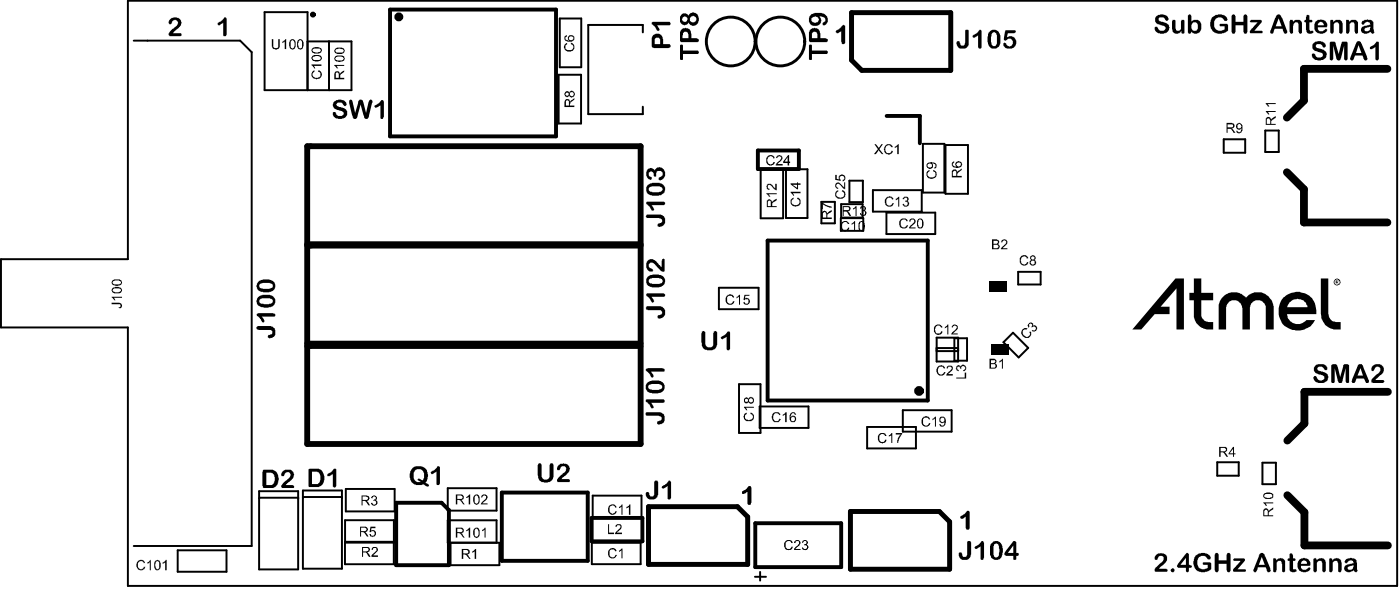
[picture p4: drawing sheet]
<svg xmlns="http://www.w3.org/2000/svg" width="119mm" height="50mm" viewBox="0 0 119 50" stroke-linecap="round" stroke-linejoin="round" font-family="sans-serif">
<g fill="none" stroke="#000" stroke-width=".17">
<path d="M10.9 .1h108.1v49.7h-108.1v-21.9h-10.8v-5.9h10.8zM11.4 3.5h9.1l.9 .9v42h-10M12.6 3.5h.1M26.2 3.5h3.7v4.2h-7.4v-6.7h3.7v6.7M28 3.5v4.2M47.6 6.4h1.9v4.1h-1.9zM47.7 1.6h1.8v4.1h-1.8zM54.7 2.8v-.7h-4.6v7.6h4.6v-.6M64.8 14.4h1.9v4.2h-1.9zM66.9 14.4h1.9v4.1h-1.9zM70 17.2h1.1v1.8h-1.1zM71.6 18.6h1.9v1h-1.9z"/>
<path d="M71.6 17.4h1.9v1.1h-1.9zM72.3 15.4h1.2v1.8h-1.2zM74.3 16.2h4.2v1.8h-4.2zM75.5 18.1h4.2v1.8h-4.2zM78.6 12.2h1.8v4.2h-1.8zM80.5 12.3h1.9v4.2h-1.9zM104.2 11.8h1.9v1.2h-1.9zM107.8 11.1h1.1v1.8h-1.1zM61.2 24.5h3.4v1.8h-3.4zM62.9 32.7h1.9v4.1h-1.9zM64.7 34.6h4.2v1.8h-4.2zM73.9 36.3h4.1v1.8h-4.1z"/>
<path d="M76.9 34.9h4.2v1.8h-4.2zM79.8 29.6h1.8M79.8 28.7h1.8v2h-1.8zM79.8 29.9h1.8M81.3 28.8h1.1v1.9h-1.1zM85.5 29.1l.8-.8 1.3 1.3-.8 .8zM86.7 23.1h1.9v1.1h-1.9zM103.7 39.3h1.8v1.2h-1.8zM107.5 39.4h1.2v1.8h-1.2zM15.1 46.8h4.2v1.8h-4.2zM22.1 41.8h3.3v6.6h-3.3zM25.4 42.3l-3.3 .1"/>
<path d="M25.8 41.7h3.3v6.7h-3.3zM29.1 42.3h-3.3M29.5 41.6h4.1v1.9h-4.1zM33.5 46.1h-4.1v1.9h4.1v-3.8h-4.1v2h4.1M38.1 41.5h4.2v1.9h-4.2zM42.3 46.2v-1.9h-4.2v1.9h4.4v1.9h-4.1v-1.9M50.4 46.2h4.2v1.8h-4.2zM50.5 42.2h4.1v1.8h-4.1zM64.3 49.1h.9M64.7 48.6v.8"/>
</g>
<path d="M26.2 12.4h28.4v8.4h-28.4zM26.2 29.4h28.4v8.4h-28.4zM26.2 20.9h28.4v8.3h-28.4z" fill="none" stroke="#000" stroke-width=".5"/>
<g fill="none" stroke="#000" stroke-width=".42">
<path d="M72.5 1.1h8.5v4.9h-7.6l-.9-.9zM55.2 43.1h7.6l.9 .9v4h-8.5zM72.4 43.5h7.6l.9 .9v4h-8.5z"/>
<circle cx="34" cy="1.4" r=".17"/>
</g>
<path d="M109.6 14.6l1.5 1.5v2.8h7.1M118.2 5.9h-7.1v2.7l-1.5 1.4M118.2 33.3h-7.1v2.7l-1.5 1.5M109.6 42.1l1.5 1.5v2.8h7.1" fill="none" stroke="#000" stroke-width=".66"/>
<path d="M33.2 .8h14.2v10.8h-14.2zM64.5 12.8h3.5v1.6h-3.5zM75.5 9.9h2.8v2.3M65.4 20.5h13.6v13.6h-13.6zM33.7 42.8h3.9l.6 .6v4.7h-4.5zM42.7 41.9h7.4v5.8h-7.4zM50.4 44h4.3v2h-4.3zM64.3 44.5h7.3v3.7h-7.3z" fill="none" stroke="#000" stroke-width=".33"/>
<g fill="#000">
<path d="M84.2 23.9h1.5v.9h-1.5z" fill-rule="evenodd"/>
<path d="M84.4 29.3h1.5v.9h-1.5z" fill-rule="evenodd"/>
</g>
<g fill="#000">
<path d="M14.4 1.7l.1-.1a.53 .53 0 0 1 .8 0 .53 .53 0 0 1 0 .8l-.6 .4h.7l.1 .2-1 .1a.24 .24 0 0 1-.1-.3 .24 .24 0 0 1 .1-.2l.3-.2a.35 .35 0 0 0 .3-.3 .35 .35 0 0 0-.2-.4l-.2 .1a.18 .18 0 0 1-.2 .3 .17 .17 0 0 1-.1-.3zM18.5 1.9l.3-.1 .2-.2a.15 .15 0 0 1 .2-.1 .15 .15 0 0 1 .1 .1v1.3a.15 .15 0 0 1-.1 .2 .15 .15 0 0 1-.2-.2v-1l-.2 .2a.13 .13 0 0 1-.2 .1 .13 .13 0 0 1-.1-.2zM23.1 3.3h.2v.5a.22 .22 0 0 0 .2 .3 .22 .22 0 0 0 .2-.3v-.5h.1v.5a.34 .34 0 0 1-.3 .4 .34 .34 0 0 1-.4-.4zM24 3.5l.4-.2v.9h-.2v-.7l-.2 .2zM26.6 6.1l.1-.1 .1 .1a.28 .28 0 0 0-.1 .4 .28 .28 0 0 0 .3 .1 .28 .28 0 0 0 .3-.2 .28 .28 0 0 0-.2-.3v-.1a.39 .39 0 0 1 .3 .5 .39 .39 0 0 1-.6 .2 .37 .37 0 0 1-.2-.6zM26.5 5.5h.9v.1h-.7l.2 .2h-.2zM28.4 8.7a.65 .65 0 0 1 1.1 .2 .21 .21 0 0 1-.2 .1 .21 .21 0 0 1-.2-.2 .33 .33 0 0 0-.5 .1l.3 .2a.55 .55 0 0 1 .6 .7 .69 .69 0 0 1-1.2-.1 .16 .16 0 0 1 .2-.2 .16 .16 0 0 1 .1 .2 .35 .35 0 0 0 .4 .2 .35 .35 0 0 0 .3-.3l-.4-.2a.5 .5 0 0 1-.5-.7zM28.5 5.5h.8v.1h-.6l.1 .2h-.1zM29.7 8.6l.1-.1h.2l.2 1.1 .3-.8a.24 .24 0 0 1 .2-.3 .24 .24 0 0 1 .3 .3l.2 .8 .2-.9a.18 .18 0 0 1 .2-.2 .18 .18 0 0 1 .1 .3l-.3 1a.24 .24 0 0 1-.2 .3 .24 .24 0 0 1-.2-.3l-.3-.9-.2 .9a.24 .24 0 0 1-.3 .3 .24 .24 0 0 1-.2-.3zM31.9 9l.5-.4a.15 .15 0 0 1 .2-.1 .15 .15 0 0 1 .1 .2v1.2a.14 .14 0 0 1-.2 .2 .13 .13 0 0 1-.1-.2v-.9l-.4 .2-.1-.1zM48.1 3.8l.1-.1 .1 .1a.28 .28 0 0 0-.1 .3 .28 .28 0 0 0 .4 .2 .25 .25 0 0 0 .2-.3 .25 .25 0 0 0-.2-.2v-.2a.42 .42 0 0 1 .2 .7 .42 .42 0 0 1-.7-.2zM55 18.3l1.1-.1a.52 .52 0 0 1 .6 .6 .52 .52 0 0 1-.7 .5v-.2l.1-.1a.22 .22 0 0 0 .3-.1 .22 .22 0 0 0-.2-.3l-1.1-.1-.1-.1z"/>
<path d="M55 17.2h1.5a.15 .15 0 0 1 .1 .1 .15 .15 0 0 1-.1 .1h-1l.2 .4a.11 .11 0 0 1-.1 .1 .11 .11 0 0 1-.1-.1l-.5-.4zM55.1 14.4a.38 .38 0 0 1 .7 .1 .51 .51 0 0 1 .7-.1 .51 .51 0 0 1 .1 .7 .26 .26 0 0 1-.2 .2 .26 .26 0 0 1-.3-.1v-.1a.32 .32 0 0 0 .3-.5 .3 .3 0 0 0-.5 0 .3 .3 0 0 0 0 .4h-.1a.25 .25 0 0 1-.2-.3 .23 .23 0 0 0-.4 0 .23 .23 0 0 0 .3 .3 .16 .16 0 0 1-.1 .3 .15 .15 0 0 1-.2-.1 .67 .67 0 0 1-.1-.8zM55.5 1.9h1.5a.15 .15 0 0 1 .1 .1 .15 .15 0 0 1-.2 .2h-.9l.2 .3-.1 .2-.3-.5-.3-.1zM57.9 3.8h.3v.5h1.2a.15 .15 0 0 1 .1 .2 .15 .15 0 0 1-.2 .1h-1.1v.5h-.2zM65.3 15.7a.49 .49 0 0 1 .7 .3v-.4h.2v.6l-.3-.1a.37 .37 0 0 0-.5-.3 .17 .17 0 0 0 0 .2 .17 .17 0 0 0 .2 .1h-.1h-.2zM65.3 13.4a.37 .37 0 0 1 .4-.2 .37 .37 0 0 1 .3 .2l-.1 .1a.27 .27 0 0 0-.4-.2 .27 .27 0 0 0-.1 .4 .29 .29 0 0 0 .2 .3 .29 .29 0 0 0 .3-.2h.1a.39 .39 0 0 1-.5 .2 .39 .39 0 0 1-.2-.5zM65.3 16.4h.9v.1h-.7l.1 .2h-.1zM66.2 13.3a.28 .28 0 0 1 .4 0 .28 .28 0 0 1-.2 .4l-.2 .2h.5v.2h-.6l.1-.3a.44 .44 0 0 0 .3-.5h-.1l-.3 .1zM67.3 17l.2-.2 .1 .1a.28 .28 0 0 0-.1 .4 .28 .28 0 0 0 .3 .1 .28 .28 0 0 0 .3-.2 .28 .28 0 0 0-.2-.3v-.1a.39 .39 0 0 1 .3 .5 .39 .39 0 0 1-.6 .2 .46 .46 0 0 1-.3-.5zM67.3 16.3h.9v.1h-.7l.1 .2h-.1zM68.9 3.8h.3v.5h1.1a.15 .15 0 0 1 .2 .2 .15 .15 0 0 1-.2 .1h-1.1v.5h-.3zM70 17.2l.5 .3 .3 .1v.1l-.3-.1-.4-.2v.4h-.1z"/>
<path d="M71.2 16.3l.1-.1 .1 .1a.27 .27 0 0 0-.2 .3 .27 .27 0 0 0 .4 .2 .28 .28 0 0 0 .3-.2 .28 .28 0 0 0-.2-.3v-.1a.39 .39 0 0 1 .3 .5 .39 .39 0 0 1-.6 .2 .42 .42 0 0 1-.2-.6zM71.2 15.6a.37 .37 0 0 1 .5 .2l.2 .1v-.4h.1v.6l-.3-.2a.27 .27 0 0 0-.2-.2 .27 .27 0 0 0-.3 .1l.2 .3a.28 .28 0 0 1-.3-.2 .28 .28 0 0 1 .1-.3zM71.1 14.9h.2v.3l.2 .1a.28 .28 0 0 1 .1-.4 .28 .28 0 0 1 .4 .2 .28 .28 0 0 1-.2 .3v-.1a.17 .17 0 0 0 .1-.2 .17 .17 0 0 0-.2-.1h-.2l.1 .4-.5-.1zM71.2 2.6l.3-.1 .3-.4 .2 .1v1.3a.18 .18 0 0 1-.2 .3 .18 .18 0 0 1-.2-.3v-.9l-.1 .1a.15 .15 0 0 1-.2 .1 .15 .15 0 0 1-.1-.2zM71.6 19a.38 .38 0 0 1 .4-.2 .38 .38 0 0 1 .3 .2h-.1a.3 .3 0 0 0-.4 0 .3 .3 0 0 0 0 .4 .25 .25 0 0 0 .2 .2 .25 .25 0 0 0 .2-.3l.1 .1a.4 .4 0 0 1-.5 .2 .4 .4 0 0 1-.2-.6zM72.5 19l.3-.2v.8h-.1v-.6l-.2 .1zM72.7 17.7l.3-.2v.9h-.1v-.7l-.2 .1zM73.3 17.6a.25 .25 0 0 1 .4 0 .25 .25 0 0 1 0 .3h-.1a.26 .26 0 0 1 0 .5 .26 .26 0 0 1-.3-.2v-.1a.16 .16 0 0 0 .2 .2 .16 .16 0 0 0 .2-.2 .16 .16 0 0 0-.2-.1v-.1a.14 .14 0 0 0 .2-.1 .14 .14 0 0 0-.2-.2 .14 .14 0 0 0-.1 .1h-.1zM74.5 12.3h.1l.3 .3 .2-.3h.1l-.3 .4 .3 .4h-.1l-.2-.3-.3 .3h-.2l.4-.4zM75.4 12.4a.38 .38 0 0 1 .3-.1 .38 .38 0 0 1 .3 .2h-.1a.29 .29 0 0 0-.4-.1 .29 .29 0 0 0-.1 .4 .28 .28 0 0 0 .3 .2 .28 .28 0 0 0 .3-.2 .14 .14 0 0 1 0 .2 .14 .14 0 0 1-.1 .1 .41 .41 0 0 1-.6-.1 .41 .41 0 0 1 .1-.6zM75.4 16.9a.33 .33 0 0 1 .4-.2 .33 .33 0 0 1 .3 .2l-.1 .1a.29 .29 0 0 0-.4-.2 .29 .29 0 0 0-.1 .4 .26 .26 0 0 0 .2 .3 .26 .26 0 0 0 .3-.2h.1a.4 .4 0 0 1-.5 .3 .4 .4 0 0 1-.2-.6zM76.2 12.5l.3-.2v.8h-.1v-.6l-.2 .1z"/>
<path d="M76.3 16.9l.3-.2v.9h-.1v-.7l-.2 .1zM76.6 18.8a.4 .4 0 0 1 .7 0h-.1a.29 .29 0 0 0-.4-.1 .29 .29 0 0 0-.1 .4 .26 .26 0 0 0 .3 .2 .26 .26 0 0 0 .2-.2l.1 .1a.42 .42 0 0 1-.5 .2 .42 .42 0 0 1-.2-.6zM76.9 16.9a.24 .24 0 0 1 .3-.2 .24 .24 0 0 1 .1 .4 .26 .26 0 0 1 0 .4 .26 .26 0 0 1-.4-.1l.1-.1a.18 .18 0 0 0 .2 .2 .18 .18 0 0 0 .1-.2 .18 .18 0 0 0-.2-.1v-.1a.14 .14 0 0 0 .2-.1 .14 .14 0 0 0-.1-.2 .14 .14 0 0 0-.2 .1h-.1zM77.5 18.7a.28 .28 0 0 1 .4 0 .28 .28 0 0 1-.1 .4l-.2 .2h.4v.1h-.6v-.1l.3-.2a.23 .23 0 0 0 .2-.2 .23 .23 0 0 0-.2-.2h-.1v.1h-.2zM79 14.6l.1-.1 .1 .1a.3 .3 0 0 0-.1 .4 .3 .3 0 0 0 .4 0 .25 .25 0 0 0 .2-.2 .25 .25 0 0 0-.2-.2v-.1l.2 .1a.38 .38 0 0 1 0 .4 .38 .38 0 0 1-.4 .2 .4 .4 0 0 1-.4-.2 .4 .4 0 0 1 .1-.4zM82.2 2.6h.3v.9a.53 .53 0 0 1-.5 .6 .53 .53 0 0 1-.6-.5 .18 .18 0 0 1 .3-.1 .18 .18 0 0 1 .1 .3l.1 .1a.24 .24 0 0 0 .3-.3zM82.8 3l.5-.2v-.2a.13 .13 0 0 1 .2-.1 .13 .13 0 0 1 .1 .2v1.3a.15 .15 0 0 1-.1 .1 .15 .15 0 0 1-.2-.1v-1l-.2 .2a.12 .12 0 0 1-.2 0 .12 .12 0 0 1-.1-.2zM85.6 2.6h.8a.13 .13 0 0 1 .1 .1 .13 .13 0 0 1-.2 .1h-.5v.4a.53 .53 0 0 1 .8 .4 .53 .53 0 0 1-.7 .5 .36 .36 0 0 1-.4-.4h.1a.39 .39 0 0 0 .5 .2 .32 .32 0 0 0 .1-.5 .32 .32 0 0 0-.4 0l-.1 .1a.14 .14 0 0 1-.2-.1 .14 .14 0 0 1 0-.2zM98.4 1.4a.62 .62 0 0 1 .7-.2 .62 .62 0 0 1 .4 .5 .23 .23 0 0 1-.4-.2 .25 .25 0 0 0-.3 0 .25 .25 0 0 0-.1 .3l.4 .1a.52 .52 0 0 1 .5 .6 .52 .52 0 0 1-.7 .4 .45 .45 0 0 1-.5-.6h.2a.36 .36 0 0 0 .3 .3 .36 .36 0 0 0 .4-.3l-.4-.2a.44 .44 0 0 1-.5-.2 .44 .44 0 0 1 0-.5zM99.9 1.7h.2v.7a.26 .26 0 0 0 .4 .2 .26 .26 0 0 0 .1-.4v-.3a.15 .15 0 0 1 .1-.2 .15 .15 0 0 1 .2 .2v.8a.14 .14 0 0 1-.2 .2 .14 .14 0 0 1-.1-.2 .42 .42 0 0 1-.5 .2 .42 .42 0 0 1-.3-.5zM103.2 1.5a.77 .77 0 0 1 1.4 .2l-.1 .1h-.2a.52 .52 0 0 0-.7-.2 .58 .58 0 0 0-.1 .8 .58 .58 0 0 0 .8 .1v-.3h-.3a.11 .11 0 0 1-.1 0 .11 .11 0 0 1 .1-.2h.5l.1 .1v.4a.86 .86 0 0 1-1.2 .2 .86 .86 0 0 1-.2-1.2zM104.9 1.3a.14 .14 0 0 1 .2-.1 .14 .14 0 0 1 .1 .2v.5h.7v-.6a.14 .14 0 0 1 .2-.1 .14 .14 0 0 1 .1 .2v1.3a.17 .17 0 0 1-.1 .2 .17 .17 0 0 1-.2-.2v-.5h-.7v.5a.17 .17 0 0 1-.1 .2 .17 .17 0 0 1-.2-.2z"/>
<path d="M106.5 1.8v-.1h1v.2l-.7 .7h.6a.11 .11 0 0 1 .2 .1 .11 .11 0 0 1-.2 .1h-.9a.11 .11 0 0 1-.1-.1 .11 .11 0 0 1 .1-.1l.6-.7h-.6zM107.8 9.4h.9v.1h-.7l.1 .2h-.1zM107.8 8.8h.9v.1h-.7l.1 .1-.1 .1zM109.9 1.7a.14 .14 0 0 1 .2 0 .14 .14 0 0 1 0 .2 .41 .41 0 0 1 .5-.2 .41 .41 0 0 1 .3 .5v.5a.15 .15 0 0 1-.2 .2 .15 .15 0 0 1-.1-.2v-.5a.24 .24 0 0 0-.2-.3 .24 .24 0 0 0-.3 .3v.5a.15 .15 0 0 1-.1 .2 .15 .15 0 0 1-.2-.2zM111.3 1.3h.1a.14 .14 0 0 1 .1 0 .14 .14 0 0 1 0 .2v.2h.2a.11 .11 0 0 1 .1 .1 .11 .11 0 0 1-.2 .1h-.1v.5a.19 .19 0 0 0 .1 .2 .19 .19 0 0 0 .2 0 .22 .22 0 0 1-.1 .3 .22 .22 0 0 1-.3-.1h-.1l-.1-.3v-.6l-.1-.1 .1-.1zM111.8 3.7h.1a.65 .65 0 0 1 1 .2l-.1 .1h-.1a.34 .34 0 0 0-.3-.2 .34 .34 0 0 0-.3 .1l.1 .2 .3 .1a.49 .49 0 0 1 .5 .5 .49 .49 0 0 1-.6 .4 .54 .54 0 0 1-.7-.5h.3a.34 .34 0 0 0 .3 .3 .34 .34 0 0 0 .4-.3l-.4-.2a.52 .52 0 0 1-.5-.6zM113.3 1.7a.14 .14 0 0 1 .2 0 .14 .14 0 0 1 .1 .2 .45 .45 0 0 1 .5-.2 .45 .45 0 0 1 .3 .5v.5l-.1 .2-.2-.1v-.6a.26 .26 0 0 0-.4-.3 .26 .26 0 0 0-.1 .4v.4l-.1 .2h-.1l-.1-.1zM113.3 3.6v-.1h.4l.1 .1 .2 1 .3-1 .4-.1 .1 .1v1.5h-.1h-.2v-1.2l-.3 1a.22 .22 0 0 1-.2 .2 .22 .22 0 0 1-.2-.2l-.2-1v1.1l-.1 .1h-.2zM114.6 1.7h.3v.2a.41 .41 0 0 1 .5-.2 .41 .41 0 0 1 .3 .5v.5a.14 .14 0 0 1-.2 .2 .13 .13 0 0 1-.1-.2v-.5a.24 .24 0 0 0-.3-.3 .24 .24 0 0 0-.2 .4v.4a.13 .13 0 0 1-.1 .2 .14 .14 0 0 1-.2-.2zM116.7 4l.4-.2a.23 .23 0 0 1 .3-.2v1.4v.1h-.3v-1.1l-.3 .2h-.1zM9.5 25.7h.6a.24 .24 0 0 1 .3 .3 .24 .24 0 0 1-.3 .2v-.1h.2l-.1-.2h-.7zM9.5 25.2h.9v.1h-.7l.1 .2h-.1z"/>
<path d="M21.8 27.8l.2-.1h.9a.53 .53 0 0 1 .5 .5 .53 .53 0 0 1-.5 .6 .18 .18 0 0 1-.1-.3 .18 .18 0 0 1 .3-.1 .21 .21 0 0 0 .1-.2 .21 .21 0 0 0-.3-.1h-.9l-.1-.1zM21.9 26.7l1.4-.1 .1 .1v.2h-1.1l.2 .3a.14 .14 0 0 1-.1 .2 .14 .14 0 0 1-.1-.1l-.4-.4zM24 40.1a.54 .54 0 0 1 .7-.2 .54 .54 0 0 1 .3 .6 .97 .97 0 0 1-.5 .6l-.2 .2h.6a.13 .13 0 0 1 .2 .1 .13 .13 0 0 1-.2 .1h-.8a.2 .2 0 0 1-.1-.2 .2 .2 0 0 1 .1-.2l.5-.4a.28 .28 0 0 0 .1-.4 .28 .28 0 0 0-.3-.2 .28 .28 0 0 0-.2 .4h-.2zM27.9 40.3l.3-.1 .2-.3h.2v1.4v.2l-.3-.1v-1.1l-.3 .2a.12 .12 0 0 1-.1 0 .12 .12 0 0 1 0-.2zM36.7 40.1l.5-.3a.14 .14 0 0 1 .2-.2 .13 .13 0 0 1 .1 .2v1.3a.15 .15 0 0 1-.2 .2 .15 .15 0 0 1-.1-.2v-1l-.2 .1a.14 .14 0 0 1-.2 .1 .14 .14 0 0 1-.1-.2zM45.8 39.4h.1a.17 .17 0 0 1 .2 0 .17 .17 0 0 1 0 .2v.8a.35 .35 0 0 0 .4 .4 .35 .35 0 0 0 .3-.4v-.8a.17 .17 0 0 1 .2-.2 .17 .17 0 0 1 .1 .2v.8a.66 .66 0 0 1-.5 .6 .66 .66 0 0 1-.8-.5zM47.5 39.7a.58 .58 0 0 1 1 0 .99 .99 0 0 1-.6 1h-.1h.7v.1v.2h-.9a.22 .22 0 0 1-.2-.2 .22 .22 0 0 1 .2-.2l.3-.4a.41 .41 0 0 0 .3-.5 .29 .29 0 0 0-.3 0 .29 .29 0 0 0-.2 .2h-.3zM55 35.1h1a.52 .52 0 0 1 .6 .5 .52 .52 0 0 1-.6 .5v-.3a.23 .23 0 0 0 .3-.1 .23 .23 0 0 0-.1-.3h-1.2v-.2zM55 34h1.4a.15 .15 0 0 1 .2 .1 .15 .15 0 0 1-.2 .2h-.9l.1 .2a.14 .14 0 0 1 .1 .1 .14 .14 0 0 1-.2 .1 .14 .14 0 0 1-.1-.1l-.2-.3a.17 .17 0 0 1-.2-.1 .17 .17 0 0 1 0-.2zM55 31.4l.2-.1h1.2l.2 .1a.14 .14 0 0 1 0 .2 .14 .14 0 0 1-.2 0h-.9l.1 .2a.16 .16 0 0 1 .1 .2 .16 .16 0 0 1-.2 .1 .16 .16 0 0 1-.1-.2l-.4-.4zM55 26.1l1.1-.1a.52 .52 0 0 1 .6 .6 .52 .52 0 0 1-.7 .5v-.2l.1-.1a.24 .24 0 0 0 .2-.1 .24 .24 0 0 0 0-.3h-1.1l-.2-.1zM55 25l1.5-.1a.15 .15 0 0 1 .1 .2 .15 .15 0 0 1-.1 .1h-1l.1 .3a.15 .15 0 0 1 .1 .1 .15 .15 0 0 1-.2 .1 .15 .15 0 0 1-.1-.2l-.4-.3z"/>
<path d="M55.1 22.3a.51 .51 0 0 1 .9 .1l.4 .4v-.7a.11 .11 0 0 1 .1-.1 .11 .11 0 0 1 .1 .2v.8a.16 .16 0 0 1-.1 .1 .16 .16 0 0 1-.2 0l-.5-.5a.3 .3 0 0 0-.2-.3 .3 .3 0 0 0-.3 .3l.1 .2a.15 .15 0 0 1 .2 .2 .15 .15 0 0 1-.2 .1 .58 .58 0 0 1-.3-.8zM59.8 28.2l.1-.1 .2 .1v.9a.34 .34 0 0 0 .3 .4 .34 .34 0 0 0 .3-.3v-.8a.18 .18 0 0 1 .2-.3 .18 .18 0 0 1 .2 .3v.8a.67 .67 0 0 1-.6 .6 .67 .67 0 0 1-.7-.5zM61.4 28.7l.4-.3 .2-.2a.14 .14 0 0 1 .1 0 .14 .14 0 0 1 .1 .2v1.3a.15 .15 0 0 1-.2 .1 .15 .15 0 0 1-.1-.2v-.9l-.3 .1a.13 .13 0 0 1-.1 .1 .13 .13 0 0 1-.1-.2zM61.9 25.2a.37 .37 0 0 1 .6 .1h-.1a.3 .3 0 0 0-.4-.1 .3 .3 0 0 0-.1 .4 .26 .26 0 0 0 .3 .2 .26 .26 0 0 0 .2-.2h.2a.41 .41 0 0 1-.7 .3 .41 .41 0 0 1 0-.7zM62.7 25.2l.3-.1v.8h-.1v-.7l-.1 .2zM63.4 35.2l.2-.1v.1a.27 .27 0 0 0-.1 .4 .27 .27 0 0 0 .3 .1 .28 .28 0 0 0 .3-.2 .28 .28 0 0 0-.2-.3v-.1a.39 .39 0 0 1 .3 .5 .39 .39 0 0 1-.5 .2 .37 .37 0 0 1-.4-.2 .37 .37 0 0 1 .1-.4zM63.4 25.1h.4v.1h-.3v.2a.28 .28 0 0 1 .3 .1 .28 .28 0 0 1-.1 .4 .28 .28 0 0 1-.4-.2h.1a.18 .18 0 0 0 .3 .1 .18 .18 0 0 0 0-.3 .18 .18 0 0 0-.2 0h-.2zM63.4 34.6h.8v.1h-.7l.2 .2h-.2zM65.8 35.2a.43 .43 0 0 1 .7 .1h-.1a.29 .29 0 0 0-.4-.1 .29 .29 0 0 0-.1 .4 .26 .26 0 0 0 .2 .2 .26 .26 0 0 0 .3-.2l.1 .1a.4 .4 0 0 1-.6 .2 .4 .4 0 0 1-.1-.6zM66.7 35.3l.3-.2v.8h-.1v-.7l-.2 .2zM74.8 37a.37 .37 0 0 1 .4-.2 .37 .37 0 0 1 .3 .3h-.1a.3 .3 0 0 0-.4-.1 .3 .3 0 0 0-.1 .5 .25 .25 0 0 0 .3 .1 .25 .25 0 0 0 .2-.2h.1a.42 .42 0 0 1-.6 .2 .42 .42 0 0 1-.1-.6zM75.7 37l.3-.2v.9h-.1v-.7l-.2 .1z"/>
<path d="M76.3 36.8h.5l-.3 .6v.3h-.1v-.3l.3-.4h-.4zM78.5 35.6h.1a.35 .35 0 0 1 .3-.2 .35 .35 0 0 1 .3 .3h-.1a.28 .28 0 0 0-.4-.2 .28 .28 0 0 0-.1 .4 .26 .26 0 0 0 .2 .3 .26 .26 0 0 0 .3-.2h.1a.41 .41 0 0 1-.5 .2 .41 .41 0 0 1-.2-.6zM79.4 35.6l.3-.2v.9h-.1v-.7l-.1 .1zM79.6 27.8a.37 .37 0 0 1 .4-.2 .37 .37 0 0 1 .3 .3h-.1a.32 .32 0 0 0-.5-.1 .32 .32 0 0 0 .1 .5l.3 .1 .1-.3 .1 .1a.4 .4 0 0 1-.6 .2 .4 .4 0 0 1-.1-.6zM79.8 31.3a.39 .39 0 0 1 .7 0l-.1 .1a.28 .28 0 0 0-.4-.2 .28 .28 0 0 0-.1 .4 .26 .26 0 0 0 .2 .3 .26 .26 0 0 0 .3-.3h.1a.39 .39 0 0 1-.5 .3 .39 .39 0 0 1-.2-.5zM80.5 27.8l.3-.2v.8h-.1v-.6l-.2 .1zM80.6 31.2a.29 .29 0 0 1 .5-.1 .29 .29 0 0 1 0 .5l-.4 .2h.5v.1h-.6l.2-.3a.23 .23 0 0 0 .2-.2 .23 .23 0 0 0-.1-.2 .14 .14 0 0 0-.1 0 .14 .14 0 0 0-.1 .2l-.1-.1zM81.1 27.7a.28 .28 0 0 1 .4 0 .28 .28 0 0 1-.1 .4l-.2 .3h.4h-.6l.1-.2 .2-.1a.27 .27 0 0 0 .1-.4h-.2v.2h-.1zM81.4 31.2l.2-.1 .2 .1a.26 .26 0 0 1 .5 0 .26 .26 0 0 1-.2 .4l-.1-.1a.18 .18 0 0 0 .2-.2 .18 .18 0 0 0-.2-.2 .18 .18 0 0 0-.1 .3h-.1a.15 .15 0 0 0-.2-.2 .15 .15 0 0 0-.1 .1 .15 .15 0 0 0 .2 .2v.1l-.2-.1-.1-.1zM81.4 32.1h.8v-.4h.1v.5h-.9zM85.1 30.7l.3-.2v.9h-.1v-.7l-.2 .1zM85.3 20.5a.28 .28 0 0 1 .5 0 .28 .28 0 0 1-.2 .4l-.2 .2h.4v.1h-.6l.2-.2a.37 .37 0 0 0 .2-.5l-.1-.1-.1 .2h-.2z"/>
<path d="M87.1 28l.1-.1h.3l-.1 .1a.3 .3 0 0 0-.3 .3 .3 .3 0 0 0 .3 .3 .24 .24 0 0 0 .3 0 .24 .24 0 0 0 0-.4h.1a.42 .42 0 0 1-.5 .5 .42 .42 0 0 1-.2-.6zM86.9 21.9a.38 .38 0 0 1 .4-.2 .38 .38 0 0 1 .3 .3h-.2a.27 .27 0 0 0-.3-.2 .27 .27 0 0 0-.2 .4 .28 .28 0 0 0 .3 .3 .28 .28 0 0 0 .3-.2h.1a.4 .4 0 0 1-.6 .2 .4 .4 0 0 1-.1-.6zM87.6 27.6a.22 .22 0 0 1 .2-.2 .22 .22 0 0 1 .2 .3 .26 .26 0 0 1 .3 .1 .26 .26 0 0 1-.1 .3l-.2 .1-.1-.1h.1a.16 .16 0 0 0 .2-.1 .16 .16 0 0 0-.1-.2 .16 .16 0 0 0-.2 .1l-.1-.1a.15 .15 0 0 0 .1-.2 .15 .15 0 0 0-.2-.1 .15 .15 0 0 0 0 .3l-.1 .1zM111.9 31.2a.71 .71 0 0 1 1.1 .1 .17 .17 0 0 1-.1 .2 .17 .17 0 0 1-.2-.2 .25 .25 0 0 0-.3-.1 .25 .25 0 0 0-.1 .3l.2 .1a.69 .69 0 0 1 .6 .5 .68 .68 0 0 1-.5 .5 .68 .68 0 0 1-.7-.3 .16 .16 0 0 1 0-.3 .18 .18 0 0 1 .3 .2 .33 .33 0 0 0 .3 .2 .33 .33 0 0 0 .3-.4l-.3-.1a.47 .47 0 0 1-.6-.6zM113.4 31.1l.1-.1h.3l.1 .1 .2 1 .3-1 .1-.1 .4 .1v1.5a.17 .17 0 0 1-.2 0 .17 .17 0 0 1-.1-.2v-1.1l-.2 1a.22 .22 0 0 1-.3 .3 .22 .22 0 0 1-.2-.3l-.2-1v1.1a.15 .15 0 0 1-.2 .2 .15 .15 0 0 1-.1-.2zM116.8 31.2l.1-.1a.53 .53 0 0 1 .6-.1 .53 .53 0 0 1 .3 .6l-.7 .7h.6a.13 .13 0 0 1 .2 .1 .14 .14 0 0 1-.2 .2l-.9-.1a.65 .65 0 0 1 .5-.7 .32 .32 0 0 0 .3-.3 .32 .32 0 0 0-.4-.3l-.1 .2a.17 .17 0 0 1-.2 .1 .17 .17 0 0 1-.1-.3zM11.7 47.7a.36 .36 0 0 1 .6 .2 .28 .28 0 0 0-.4-.1 .28 .28 0 0 0-.2 .4 .26 .26 0 0 0 .3 .2 .26 .26 0 0 0 .3-.2h.1a.42 .42 0 0 1-.6 .2 .42 .42 0 0 1-.1-.6zM12.5 47.8l.3-.2v.9v-.7l-.3 .2zM13.9 47.8l.3-.2v.9h-.1v-.7l-.2 .2zM31.7 42.2a.23 .23 0 0 1 .3 0 .23 .23 0 0 1 0 .3 .26 .26 0 0 1 0 .5 .26 .26 0 0 1-.4-.2h.1a.17 .17 0 0 0 .2 .1 .17 .17 0 0 0 .1-.2 .17 .17 0 0 0-.1-.1v-.1a.13 .13 0 0 0 .1-.2 .13 .13 0 0 0-.2-.1 .13 .13 0 0 0-.1 .2l-.1-.1zM31.7 46.6a.28 .28 0 0 1 .4 0 .28 .28 0 0 1-.1 .4l-.2 .2h.4v.2h-.6l.2-.3a.34 .34 0 0 0 .2-.5h-.2v.2l-.2-.1zM31.6 44.8h.4v.1h-.4v.2a.29 .29 0 0 1 .4 .1 .29 .29 0 0 1-.2 .4 .29 .29 0 0 1-.3-.2h.1a.19 .19 0 0 0 .2 .1 .19 .19 0 0 0 .1-.2 .19 .19 0 0 0-.3-.1l-.1 .1z"/>
<path d="M39.7 45.1l.3-.2v.8h-.1v-.7l-.1 .2zM39.7 42.3l.3-.2v.8h-.1v-.7l-.1 .1zM40.2 46.9l.4-.2v.8h-.2v-.6l-.2 .1zM41 42.1a.29 .29 0 0 1 .5 .1 .29 .29 0 0 1-.2 .4l-.2 .2h.4v.1h-.6l.2-.3a.34 .34 0 0 0 .2-.5l-.3 .2zM41.1 45.1l.3-.2v.8h-.1v-.7l-.2 .2zM51.8 44.6h.1v.7h.4v.1h-.5zM51.8 46.8h.1a.35 .35 0 0 1 .3-.2 .35 .35 0 0 1 .3 .3h-.1a.28 .28 0 0 0-.4-.1 .28 .28 0 0 0-.1 .4 .26 .26 0 0 0 .3 .2 .26 .26 0 0 0 .2-.2h.2a.4 .4 0 0 1-.6 .3 .4 .4 0 0 1-.2-.6zM51.8 43.1a.38 .38 0 0 1 .4-.2 .38 .38 0 0 1 .3 .3h-.1a.28 .28 0 0 0-.4-.2 .28 .28 0 0 0-.1 .4 .26 .26 0 0 0 .3 .3 .26 .26 0 0 0 .2-.2h.2a.41 .41 0 0 1-.6 .2 .41 .41 0 0 1-.2-.6zM52.5 44.6a.27 .27 0 0 1 .3 0 .27 .27 0 0 1 .1 .2v.2l-.3 .3h.4v.1h-.6l.1-.2a.42 .42 0 0 0 .3-.5h-.2l-.1 .1h-.1zM52.7 46.8l.3-.2v.9h-.1v-.7l-.1 .1zM52.7 43.1l.3-.2v.9h-.1v-.7l-.2 .1zM53.4 43.1l.3-.2v.9h-.1v-.7l-.2 .1z"/>
<path d="M55.7 41l.1-.1a.17 .17 0 0 1 .2 0 .17 .17 0 0 1 .1 .1v.9a.53 .53 0 0 1-.6 .6 .53 .53 0 0 1-.5-.6 .17 .17 0 0 1 .3 0 .17 .17 0 0 1 0 .2 .23 .23 0 0 0 .3 .1 .23 .23 0 0 0 .1-.3zM56.4 41.3l.3-.1 .2-.3h.2l.1 1.4a.15 .15 0 0 1-.2 .2 .15 .15 0 0 1-.1-.2v-1l-.3 .2a.12 .12 0 0 1-.2 0 .12 .12 0 0 1 0-.2zM63.2 41.8l.3-.2 .2-.3a.17 .17 0 0 1 .2 0 .17 .17 0 0 1 .1 .2v1.3l-.1 .1a.17 .17 0 0 1-.2 0 .17 .17 0 0 1 0-.1v-1l-.2 .2a.15 .15 0 0 1-.3 0 .15 .15 0 0 1 0-.2zM66.8 46.1a.37 .37 0 0 1 .4-.2 .37 .37 0 0 1 .3 .3h-.1a.3 .3 0 0 0-.4-.1 .3 .3 0 0 0 0 .5 .25 .25 0 0 0 .2 .1 .25 .25 0 0 0 .2-.2h.1a.4 .4 0 0 1-.5 .3 .4 .4 0 0 1-.2-.5zM67.7 46a.28 .28 0 0 1 .4 0 .28 .28 0 0 1-.1 .4l-.2 .3h.4v.1h-.6l.2-.3a.34 .34 0 0 0 .2-.5l-.4 .2zM68.4 46a.23 .23 0 0 1 .3 0 .23 .23 0 0 1 0 .3 .27 .27 0 0 1 0 .5 .27 .27 0 0 1-.4-.2h.1a.17 .17 0 0 0 .2 .1 .17 .17 0 0 0 .1-.2 .17 .17 0 0 0-.2-.1v-.1a.14 .14 0 0 0 .2-.2 .14 .14 0 0 0-.2-.1 .14 .14 0 0 0-.1 .2l-.1-.1zM81.8 44l.5-.4a.15 .15 0 0 1 .2-.2 .15 .15 0 0 1 .1 .2v1.4h-.1a.17 .17 0 0 1-.2 0 .17 .17 0 0 1-.1-.1v-1a.25 .25 0 0 1-.2 .2 .25 .25 0 0 1-.2-.1zM82.4 46h.1a.17 .17 0 0 1 .1 0 .17 .17 0 0 1 .1 .2v.8a.53 .53 0 0 1-.5 .6 .53 .53 0 0 1-.5-.6 .25 .25 0 0 1 .3 .3l.2 .1 .2-.2zM83 46.5l.4-.2 .2-.2a.09 .09 0 0 1 .1-.1 .09 .09 0 0 1 .1 .1v1.3l-.1 .2h-.2v-1.1l-.2 .1a.17 .17 0 0 1-.1 .1 .17 .17 0 0 1-.2-.2zM98.4 47.3a.55 .55 0 0 1 .7-.3 .55 .55 0 0 1 .3 .7l-.7 .6 .7 .1a.11 .11 0 0 1 .1 .2 .11 .11 0 0 1-.2 0h-.8a.25 .25 0 0 1-.2-.2 .25 .25 0 0 1 .3-.2l.1-.2a.67 .67 0 0 0 .4-.6 .32 .32 0 0 0-.4-.1 .32 .32 0 0 0-.1 .3h-.3zM101.8 47.3a.79 .79 0 0 1 1.3 .1v.2h-.2a.49 .49 0 0 0-.7-.2 .49 .49 0 0 0-.2 .7 .54 .54 0 0 0 .9 .2v-.3h-.3a.11 .11 0 0 1-.2-.1 .11 .11 0 0 1 .2-.1h.5l.1 .1v.4a.56 .56 0 0 1-.7 .4h-.1a.86 .86 0 0 1-.6-1.4zM103.5 47.1l.2-.1 .1 .2v.5h.7v-.5a.17 .17 0 0 1 .1-.2 .17 .17 0 0 1 .2 .2v1.3a.17 .17 0 0 1-.2 .2 .17 .17 0 0 1-.1-.2v-.5h-.7v.5a.17 .17 0 0 1-.2 .2 .17 .17 0 0 1-.1-.2z"/>
<path d="M105 47.6l.1-.1h.8a.15 .15 0 0 1 .1 .1 .15 .15 0 0 1-.1 .2l-.5 .6h.6a.11 .11 0 0 1 .1 .1 .11 .11 0 0 1-.1 .1h-.9a.65 .65 0 0 1 .3-.6l.3-.3h-.6zM107.6 42.7h.8v.1h-.6l.1 .1-.1 .1zM108.4 47.5h.3v.2a.41 .41 0 0 1 .5-.2 .41 .41 0 0 1 .3 .5v.5a.14 .14 0 0 1-.2 .2 .13 .13 0 0 1-.1-.2v-.5a.24 .24 0 0 0-.3-.3 .24 .24 0 0 0-.2 .4v.4a.14 .14 0 0 1-.2 .2 .13 .13 0 0 1-.1-.2zM109.8 47.1h.3v.4h.1a.11 .11 0 0 1 .1 .1 .11 .11 0 0 1-.1 .1h-.1v.5a.16 .16 0 0 0 .1 .2 .16 .16 0 0 0 .2 0v.1a.12 .12 0 0 1 0 .1 .12 .12 0 0 1-.1 .1 .33 .33 0 0 1-.5-.4v-.6h-.1a.12 .12 0 0 1 0-.2 .12 .12 0 0 1 .1 0zM111.9 47.5l.1-.1 .2 .3a.42 .42 0 0 1 .5-.2 .42 .42 0 0 1 .2 .5v.5l-.1 .2-.2-.1v-.6a.26 .26 0 0 0-.3-.3 .26 .26 0 0 0-.1 .4v.5l-.3 .1v-.1zM113.2 47.5l.1-.1 .2 .3a.41 .41 0 0 1 .5-.2 .41 .41 0 0 1 .3 .5l-.1 .5a.13 .13 0 0 1-.1 .2 .13 .13 0 0 1-.1-.2v-.5a.25 .25 0 0 0-.3-.3 .25 .25 0 0 0-.2 .4v.4a.14 .14 0 0 1-.2 .2 .13 .13 0 0 1-.1-.2z"/>
<path d="M24.8 3.5v.1a.46 .46 0 0 0 .1 .5 .43 .43 0 0 0 0-.7zM24.7 3.5a.32 .32 0 0 1 .4-.1 .32 .32 0 0 1 .1 .4 .29 .29 0 0 1-.3 .4 .29 .29 0 0 1-.3-.4z"/>
<path d="M25.4 3.5a.46 .46 0 0 0 .2 .6 .4 .4 0 0 0 .1-.5l-.1-.2zM25.3 3.5a.33 .33 0 0 1 .5-.1 .33 .33 0 0 1 .1 .5 .29 .29 0 0 1-.4 .3 .29 .29 0 0 1-.2-.4z"/>
<path d="M26.6 4.9l.1 .2h.1a.46 .46 0 0 0 .5-.2 .51 .51 0 0 0-.7 0zM26.5 4.8l.3-.1a.42 .42 0 0 1 .6 .3v.1a.47 .47 0 0 1-.5 .1 .47 .47 0 0 1-.4-.4z"/>
<path d="M26.6 4.2a.4 .4 0 0 0 .6 .2 .18 .18 0 0 0 .1-.2 .18 .18 0 0 0-.3-.1zM26.6 4.1a.51 .51 0 0 1 .8 .2 .51 .51 0 0 1-.9 0z"/>
<path d="M28.6 4.9v.2h.2a.35 .35 0 0 0 .5-.2l-.2-.1h-.4zM28.5 4.8l.3-.1a.35 .35 0 0 1 .4 0 .35 .35 0 0 1 .1 .4l-.2 .1a.54 .54 0 0 1-.5-.1h-.1z"/>
<path d="M28.6 4.2v.2l.2 .1a.35 .35 0 0 0 .5-.2l-.3-.2zM28.5 4.2l.2-.2a.42 .42 0 0 1 .7 .4 .54 .54 0 0 1-.9-.1z"/>
<path d="M28.6 6.2v.4h.3v-.4h-.1zM28.5 6.2a.26 .26 0 0 1 .3-.1 .26 .26 0 0 1 .2 .2v-.1l.3-.2v.1l-.3 .3v.2h.3v.1h-.8z"/>
<path d="M48.1 3.1l.2-.1-.1 .1a.2 .2 0 0 0 0 .3 .2 .2 0 0 0 .3 .1 .28 .28 0 0 1 0-.5 .28 .28 0 0 1 .4 .2 .28 .28 0 0 1-.3 .3 .38 .38 0 0 1-.4 0 .38 .38 0 0 1-.1-.4zM48.5 3.2a.17 .17 0 0 0 .3 0 .17 .17 0 0 0-.3 0z"/>
<path d="M48.2 8a.14 .14 0 0 0 .2 0 .14 .14 0 0 0-.2 0zM48.5 8a.2 .2 0 0 0 .4 0 .2 .2 0 0 0-.4 0zM48.1 7.8h.1a.14 .14 0 0 1 .2 0 .14 .14 0 0 1 .1 .1 .27 .27 0 0 1 .4-.1 .27 .27 0 0 1 0 .4 .27 .27 0 0 1-.4-.1 .21 .21 0 0 1-.4 .1 .21 .21 0 0 1 0-.3z"/>
<path d="M48.2 8.6v.4h.3v-.4l-.2-.1zM48.1 8.5a.27 .27 0 0 1 .3-.1 .27 .27 0 0 1 .2 .2l.3-.3v.2l-.4 .4v.1h.4v.1h-.8z"/>
<path d="M55.3 15.9v.1a.31 .31 0 0 0 .3 .4h.1a.7 .7 0 0 0 .7-.3 .77 .77 0 0 0-.8-.3zM55.1 15.8l.5-.2h.6a.54 .54 0 0 1 .4 .6 .54 .54 0 0 1-.6 .4h-.4a.55 .55 0 0 1-.5-.2 .55 .55 0 0 1 0-.6z"/>
<path d="M55.8 3.2v.6h.4v-.5l-.1-.1zM55.6 3.1a.52 .52 0 0 1 .6-.2 .52 .52 0 0 1 .3 .6v.3h.5l.1 .2-.2 .1-1.3-.1z"/>
<path d="M58.1 1.6a.23 .23 0 0 0 .4 0 .23 .23 0 0 0-.4 0zM58.8 1.6a.27 .27 0 0 0 .5 0 .27 .27 0 0 0-.5 0zM58 1.3a.39 .39 0 0 1 .6 .1 .48 .48 0 0 1 .6-.3 .48 .48 0 0 1 .3 .6 .46 .46 0 0 1-.3 .5 .46 .46 0 0 1-.6-.3 .41 .41 0 0 1-.5 .2 .41 .41 0 0 1-.2-.6z"/>
<path d="M58.2 2.8l-.1 .4h.5v-.2a.26 .26 0 0 0-.1-.3 .26 .26 0 0 0-.3 .1zM58 2.5a.53 .53 0 0 1 .6-.1 .53 .53 0 0 1 .3 .6v.2l.5 .1a.15 .15 0 0 1 .1 .2 .15 .15 0 0 1-.2 .1h-1.3l-.1-.1v-.8z"/>
<path d="M65.4 17.2v.3h.2v-.3a.13 .13 0 0 0-.1-.2 .13 .13 0 0 0-.1 .2zM65.3 17.1a.27 .27 0 0 1 .3-.1 .27 .27 0 0 1 .2 .2l.4-.3v.1l-.4 .3v.2h.4v.1h-.9z"/>
<path d="M67.1 13.4l-.3 .3h.3zM67.1 13.2h.1v.5h.1l-.1 .4h-.1v-.2h-.4v-.2z"/>
<path d="M67.5 15.7l.4 .3v-.3zM67.3 15.6h.6l.1-.1v.1h.2v.1h-.2v.4h-.1l-.6-.4z"/>
<path d="M69.1 1.6a.3 .3 0 0 0 .4 .3 .3 .3 0 0 0 .1-.5h-.2zM69.1 1.2l.3-.1h.3a.61 .61 0 0 1 .7 .2 .61 .61 0 0 1-.1 .8l-.2 .1a.24 .24 0 0 1 .2-.4 .39 .39 0 0 0-.5-.4 .49 .49 0 0 1-.1 .8 .49 .49 0 0 1-.8-.3 .57 .57 0 0 1 .2-.7z"/>
<path d="M69.2 2.8v.4h.4v-.2a.26 .26 0 0 0-.1-.3 .26 .26 0 0 0-.3 .1zM69 2.5h.1a.51 .51 0 0 1 .5 0 .51 .51 0 0 1 .3 .5v.2l.4 .1a.15 .15 0 0 1 .2 .1 .15 .15 0 0 1-.2 .2h-1.3l-.1-.1v-.8z"/>
<path d="M70.1 18.1v.4h.3l-.1-.3a.13 .13 0 0 0-.1-.2 .13 .13 0 0 0-.1 .1zM70 18a.25 .25 0 0 1 .3-.1 .25 .25 0 0 1 .2 .3l.3-.3v.1l-.3 .2v.3h.3v.1h-.8z"/>
<path d="M71.9 17.6v.3h.3a.13 .13 0 0 0 .1-.2 .13 .13 0 0 0-.1-.1zM71.8 17.5h.4a.24 .24 0 0 1 .3 .2 .24 .24 0 0 1-.3 .3h.1l.2 .4h-.1l-.3-.4h-.2v.4h-.1z"/>
<path d="M73.3 18.9l-.1 .1a.41 .41 0 0 0 .2 .6 .47 .47 0 0 0-.1-.7zM73.2 18.9a.33 .33 0 0 1 .4 0 .33 .33 0 0 1 .1 .4h-.1a.28 .28 0 0 1-.3 .4 .28 .28 0 0 1-.2-.4z"/>
<path d="M78.2 18.7v.1a.46 .46 0 0 0 .2 .5 .43 .43 0 0 0 .1-.5l-.1-.1zM78.2 18.6a.38 .38 0 0 1 .4 .1 .38 .38 0 0 1 .1 .4 .29 .29 0 0 1-.4 .3 .29 .29 0 0 1-.2-.4z"/>
<path d="M79 14.1a.2 .2 0 0 0 .4 0 .2 .2 0 0 0-.4 0zM79 13.9l.2-.1h.2a.27 .27 0 0 1 .3 .2 .27 .27 0 0 1-.1 .3l-.1-.1a.18 .18 0 0 0 .2-.2 .18 .18 0 0 0-.3-.1 .28 .28 0 0 1 0 .4 .28 .28 0 0 1-.4 0 .28 .28 0 0 1 0-.4z"/>
<path d="M81.1 13.8l.2-.1-.1 .1a.21 .21 0 0 0 0 .3 .21 .21 0 0 0 .3 .1 .27 .27 0 0 1 0-.4 .27 .27 0 0 1 .4 0 .27 .27 0 0 1-.1 .4h-.1a.54 .54 0 0 1-.6-.1zM81.4 14a.2 .2 0 0 0 .4 0 .2 .2 0 0 0-.4 0z"/>
<path d="M81.2 14.6v.4h.2v-.4a.11 .11 0 0 0-.1-.1 .11 .11 0 0 0-.1 .1zM81.1 14.5l.1-.1h.2l.1 .2 .4-.3v.2l-.4 .3v.2h.4v.1h-.8z"/>
<path d="M84.5 2.8l-.1 .5a.42 .42 0 0 0 .3 .6 1.09 1.09 0 0 0 .2-1l-.2-.2zM84.2 2.8a.58 .58 0 0 1 .7-.2 .58 .58 0 0 1 .3 .7v.2a.56 .56 0 0 1-.5 .6 .56 .56 0 0 1-.6-.6z"/>
<path d="M101.5 2a.43 .43 0 0 0 .3 .7 .41 .41 0 0 0 .2-.4 .41 .41 0 0 0-.2-.4zM101.2 1.3l.1-.1 .1 .1 .1 .6a.51 .51 0 0 1 .6-.1 .51 .51 0 0 1 .2 .6 .47 .47 0 0 1-.3 .4 .47 .47 0 0 1-.5-.1 .15 .15 0 0 1-.2 .2 .15 .15 0 0 1-.1-.2z"/>
<path d="M104.6 10.6v.2h.4v-.2zM104.5 10.5h.3a.24 .24 0 0 1 .3 .2 .24 .24 0 0 1-.2 .2l.3 .4h-.1l-.3-.3h-.2v.3h-.1z"/>
<path d="M105.4 10.6a.18 .18 0 0 0 .1 .3 .18 .18 0 0 0 .2-.2 .18 .18 0 0 0-.2-.2zM105.3 10.6a.33 .33 0 0 1 .4 0 .33 .33 0 0 1 .1 .4 .28 .28 0 0 1-.2 .3 .28 .28 0 0 1-.3-.2h.1a.18 .18 0 0 0 .2 .1 .18 .18 0 0 0 .1-.2v-.1a.27 .27 0 0 1-.3 .1 .27 .27 0 0 1-.1-.4z"/>
<path d="M107.9 10.2v.3h.3l-.1-.3a.13 .13 0 0 0-.1-.2 .13 .13 0 0 0-.1 .2zM107.8 10.1a.25 .25 0 0 1 .3-.1 .25 .25 0 0 1 .2 .2v-.1l.4-.2v.1l-.4 .3v.2h.4v.1h-.9z"/>
<path d="M108.9 1.6l-.2 .6h.5zM108.7 1.4a.29 .29 0 0 1 .3-.1 .29 .29 0 0 1 .2 .2l.4 1.1a.18 .18 0 0 1-.1 .3 .18 .18 0 0 1-.2-.2l-.1-.3h-.6l-.1 .3a.17 .17 0 0 1-.1 .2 .17 .17 0 0 1-.2-.1 .17 .17 0 0 1 0-.2z"/>
<path d="M112.2 2v.2h.5a.26 .26 0 0 0-.1-.3 .26 .26 0 0 0-.4 .1zM112 1.9l.2-.1a.5 .5 0 0 1 .6-.1 .5 .5 0 0 1 .2 .6h-.8a.33 .33 0 0 0 .3 .4 .33 .33 0 0 0 .4-.2 .12 .12 0 0 1 .1 0 .12 .12 0 0 1 0 .2 .63 .63 0 0 1-.9 0 .63 .63 0 0 1-.1-.8z"/>
<path d="M115.7 3.8l-.2 .7h.5zM115.5 3.6a.27 .27 0 0 1 .3-.1 .27 .27 0 0 1 .2 .3l.4 1a.2 .2 0 0 1 0 .4 .21 .21 0 0 1-.3-.3l-.1-.2h-.6l-.1 .2a.18 .18 0 0 1-.2 .3 .21 .21 0 0 1-.1-.4z"/>
<path d="M116.2 2.4a.26 .26 0 0 0 .3 .2 .26 .26 0 0 0 .2-.3h-.1zM116 1.8h.1a.7 .7 0 0 1 .9 .1v.8a.14 .14 0 0 1-.1 .2 .14 .14 0 0 1-.1-.2h-.1a.45 .45 0 0 1-.4 .2 .45 .45 0 0 1-.4-.4 .54 .54 0 0 1 .7-.3l.1-.1a.3 .3 0 0 0-.3-.2 .3 .3 0 0 0-.3 .2l-.1-.1z"/>
<path d="M9.6 24.6a.24 .24 0 0 0 .1 .3 .24 .24 0 0 0 .3 0 .18 .18 0 0 0 .3-.1 .18 .18 0 0 0-.2-.3zM9.5 24.5a.54 .54 0 0 1 .9 .2 .51 .51 0 0 1-.7 .2l-.2-.2z"/>
<path d="M9.6 24a.38 .38 0 0 0 .5 .2h.1a.2 .2 0 0 0 0-.3 .2 .2 0 0 0-.2 0h-.2zM9.5 23.9l.3-.1a.41 .41 0 0 1 .6 .3 .5 .5 0 0 1-.5 .2 .5 .5 0 0 1-.4-.3z"/>
<path d="M22.1 25.5a.33 .33 0 0 0 .4 .4 .7 .7 0 0 0 .7-.2 .31 .31 0 0 0-.1-.3 .31 .31 0 0 0-.4 0h-.4zM21.9 25.3h.1a1.08 1.08 0 0 1 1.4 .1 .6 .6 0 0 1-.7 .8h-.2a.55 .55 0 0 1-.6-.3 .55 .55 0 0 1 0-.6z"/>
<path d="M22.1 24.2a.33 .33 0 0 0 .5 .4 .61 .61 0 0 0 .6-.2 .45 .45 0 0 0-.6-.3zM22 24a1.09 1.09 0 0 1 1.4 .1 .62 .62 0 0 1-.1 .6 .62 .62 0 0 1-.7 .2 .6 .6 0 0 1-.7-.7z"/>
<path d="M35.3 40l-.1 .3a.49 .49 0 0 0 .1 .5 .49 .49 0 0 0 .5 .2l-.1-.1a.11 .11 0 0 1-.1-.1 .11 .11 0 0 1 .1-.1 .11 .11 0 0 1 .1 .1h.1a.12 .12 0 0 0 .2 0 .12 .12 0 0 0 0-.1v-.1a.49 .49 0 0 0-.2-.6 .49 .49 0 0 0-.6 0zM35.1 39.8l.3-.1h.2a.82 .82 0 0 1 .8 .4 .82 .82 0 0 1-.2 .9l.2 .1a.15 .15 0 0 1 .1 .2 .15 .15 0 0 1-.1 .1 .15 .15 0 0 1-.2-.1 .16 .16 0 0 0-.1-.1 .16 .16 0 0 0-.2 .1 .86 .86 0 0 1-.9-.5 .86 .86 0 0 1 .1-1z"/>
<path d="M55.3 32.7v.1a.31 .31 0 0 0 .3 .4h.1a.59 .59 0 0 0 .7-.3 .65 .65 0 0 0-.8-.2zM55.1 32.5l.4-.1h.4a.56 .56 0 0 1 .7 .5 .56 .56 0 0 1-.7 .6h-.2a.57 .57 0 0 1-.6-.3 .57 .57 0 0 1 0-.7z"/>
<path d="M55.3 23.8a.44 .44 0 0 0 .6 .3 .41 .41 0 0 0 .5-.2v-.1a1.05 1.05 0 0 0-1.1 0zM55.1 23.6l.3-.2 .7-.1a.56 .56 0 0 1 .5 .7 .56 .56 0 0 1-.7 .4h-.3a.54 .54 0 0 1-.5-.2 .54 .54 0 0 1 0-.6z"/>
<path d="M63.5 34a.14 .14 0 0 0 .2 0 .14 .14 0 0 0-.2 0zM63.8 34a.2 .2 0 0 0 .4 0 .2 .2 0 0 0-.4 0zM63.4 33.9l.1-.1 .2 .1a.26 .26 0 0 1 .4 0 .26 .26 0 0 1 0 .4h-.2l-.2-.1a.23 .23 0 0 1-.3 0 .23 .23 0 0 1 0-.3z"/>
<path d="M67.3 35.2a.28 .28 0 0 1 .3-.1 .28 .28 0 0 1 .2 .2l-.1-.1a.22 .22 0 0 0-.3 0 .22 .22 0 0 0-.1 .3 .26 .26 0 0 1 .4 0 .26 .26 0 0 1 0 .4 .26 .26 0 0 1-.4-.2zM67.3 35.6a.2 .2 0 0 0 .4 0 .2 .2 0 0 0-.4 0z"/>
<path d="M80.1 35.7a.17 .17 0 0 0 .3 0 .17 .17 0 0 0-.3 0zM80.1 35.5a.38 .38 0 0 1 .4 .1 .38 .38 0 0 1 0 .5 .26 .26 0 0 1-.2 .2 .26 .26 0 0 1-.3-.2h.1a.2 .2 0 0 0 .3 .1 .2 .2 0 0 0 0-.3 .27 .27 0 0 1-.4 0 .27 .27 0 0 1 .1-.4z"/>
<path d="M84.4 30.6v.3h.3l.1-.1-.1-.2zM84.4 31v.3l.4-.1-.1-.2zM84.3 30.5h.3a.22 .22 0 0 1 .3 .2 .22 .22 0 0 1-.2 .2 .22 .22 0 0 1 .2 .3 .22 .22 0 0 1-.3 .2h-.3z"/>
<path d="M84.6 20.5v.2h.3l.1-.1a.11 .11 0 0 0 0-.1 .11 .11 0 0 0-.2 0zM84.6 20.8v.3h.3a.15 .15 0 0 0 .1-.2 .15 .15 0 0 0-.2-.1zM84.5 20.4h.3a.24 .24 0 0 1 .3 .1 .24 .24 0 0 1-.1 .3 .22 .22 0 0 1 .1 .2 .22 .22 0 0 1-.2 .2h-.4z"/>
<path d="M87.8 21.9a.15 .15 0 0 0 .3 0 .15 .15 0 0 0-.3 0zM87.8 22.3a.16 .16 0 0 0 .3 0 .16 .16 0 0 0-.3 0zM87.7 21.8a.24 .24 0 0 1 .4-.1 .24 .24 0 0 1 0 .4 .26 .26 0 0 1 .1 .4 .26 .26 0 0 1-.4 .1 .26 .26 0 0 1-.1-.3l.2-.2-.2-.1z"/>
<path d="M104 38.1v.3h.2a.16 .16 0 0 0 .2-.2 .16 .16 0 0 0-.2-.1zM103.8 38h.5a.23 .23 0 0 1 .2 .2 .23 .23 0 0 1-.2 .3l.3 .4h-.1l-.3-.4h-.2v.4h-.2z"/>
<path d="M105 38.2l-.3 .4h.3zM105 38h.1v.6h.1h-.1v.3h-.1v-.3h-.4z"/>
<path d="M113.8 23.9l.1 .1zM113.8 23.9h.2l-.1 .1 .1 .1-.1-.1-.1 .1zM113.7 24a.23 .23 0 0 0 .4 0 .23 .23 0 0 0-.4 0zM113.6 24a.3 .3 0 0 1 .6 0 .3 .3 0 0 1-.6 0zM104 25.4a1.35 1.35 0 0 1 2.1-.1 1.35 1.35 0 0 1 1.5-.3 1.35 1.35 0 0 1 .9 1.2v1.8h-.7v-1.8a.68 .68 0 0 0-.7-.7 .68 .68 0 0 0-.6 .7v1.8h-.7v-1.8a.7 .7 0 0 0-.7-.7 .7 .7 0 0 0-.7 .7v1.8h-.6v-2.1zM109.8 25.7l-.2 .4h1.8a.89 .89 0 0 0-1.6-.4zM100.1 23.7h.7v4.3h-.6v-3.5l-1.3 1.6h.7v.6h-1.3l-1.1 1.3h-.8zM112.5 23.7h.6l.1 3.2 .3 .4 .7 .1v.6h-.4a1.36 1.36 0 0 1-1.2-.8l-.1-.5zM101.7 23.7h.6v1.2h1v.6h-1l.1 1.5 .3 .3 .6 .1v.6h-.3a1.3 1.3 0 0 1-1.3-1.3v-1.2h-.4v-.6h.4zM109.3 25.3a1.69 1.69 0 0 1 2.7 .5l.1 .9h-2.5a.92 .92 0 0 0 .7 .8 .92 .92 0 0 0 1-.3h.7a1.66 1.66 0 0 1-2.5 .6 1.66 1.66 0 0 1-.2-2.5z"/>
<path d="M115.9 31.3l-.3 .6h.5zM115.6 31.1a.27 .27 0 0 1 .3-.1 .27 .27 0 0 1 .2 .3l.5 1a.18 .18 0 0 1-.1 .3 .18 .18 0 0 1-.2-.2l-.1-.2h-.7v.2a.18 .18 0 0 1-.3 .2 .17 .17 0 0 1 0-.3z"/>
<path d="M13.3 47.8a.45 .45 0 0 0 .1 .6l.2-.1a.55 .55 0 0 0-.2-.6zM13.2 47.7a.33 .33 0 0 1 .4 0 .33 .33 0 0 1 .1 .5 .29 .29 0 0 1-.3 .3 .29 .29 0 0 1-.3-.4z"/>
<path d="M22.7 40.2v1.1h.3a.54 .54 0 0 0 .4-.8l-.2-.3zM22.4 40l.6-.1a.8 .8 0 0 1 .7 .6 .8 .8 0 0 1-.2 .8l-.2 .2h-.9z"/>
<path d="M26.6 40.1v1.1h.3a.49 .49 0 0 0 .3-.8v-.2l-.2-.1zM26.3 39.9h.7a.81 .81 0 0 1 .5 1.3l-.3 .2h-.9z"/>
<path d="M30.8 44.9v.3h.3l.1-.1v-.1l-.1-.1zM30.7 44.8h.3a.24 .24 0 0 1 .3 .2 .24 .24 0 0 1-.2 .3l.3 .3h-.1l-.3-.3h-.2v.3h-.1z"/>
<path d="M30.9 42.2v.3h.4v-.1a.12 .12 0 0 0 0-.1 .12 .12 0 0 0-.1-.1zM30.8 42.1h.4a.24 .24 0 0 1 .3 .2 .24 .24 0 0 1-.3 .3l.3 .4h-.1l-.3-.4h-.2v.4h-.1z"/>
<path d="M30.9 46.6v.3h.4a.13 .13 0 0 0 .1-.2 .13 .13 0 0 0-.2-.1zM30.8 46.5h.4a.24 .24 0 0 1 .3 .2 .24 .24 0 0 1-.2 .3l.3 .4h-.2l-.2-.4h-.3v.4h-.1z"/>
<path d="M38.9 45v.3h.3a.16 .16 0 0 0 .2-.2 .16 .16 0 0 0-.2-.1zM38.8 44.9h.4a.23 .23 0 0 1 .3 .2 .23 .23 0 0 1-.2 .2l.3 .4h-.1l-.4-.4h-.2v.4h-.1z"/>
<path d="M38.9 42.1v.3h.3a.16 .16 0 0 0 .2-.1 .16 .16 0 0 0-.2-.2zM38.8 42.1h.4a.23 .23 0 0 1 .3 .2 .23 .23 0 0 1-.2 .2l.3 .4h-.1l-.4-.4h-.2v.4h-.1z"/>
<path d="M39.5 46.8v.3l.4-.1a.17 .17 0 0 0 0-.2 .17 .17 0 0 0-.2 0zM39.3 46.7h.4a.24 .24 0 0 1 .3 .2 .24 .24 0 0 1-.2 .3l.3 .3h-.1l-.4-.3h-.1v.3h-.2z"/>
<path d="M40.5 45a.54 .54 0 0 0 .1 .7 .43 .43 0 0 0 0-.7zM40.3 45a.32 .32 0 0 1 .5 0 .32 .32 0 0 1 0 .4 .28 .28 0 0 1-.2 .4 .28 .28 0 0 1-.3-.3z"/>
<path d="M40.5 42.2l-.1 .1a.55 .55 0 0 0 .2 .6 .43 .43 0 0 0 0-.8zM40.3 42.2a.32 .32 0 0 1 .5-.1 .32 .32 0 0 1 0 .5 .28 .28 0 0 1-.2 .3 .28 .28 0 0 1-.3-.3z"/>
<path d="M84.7 46.3l-.1 .5a.43 .43 0 0 0 .3 .6l.2-.2v-.4a.48 .48 0 0 0-.3-.6zM84.4 46.2a.59 .59 0 0 1 .7-.1 .59 .59 0 0 1 .3 .6v.2a.59 .59 0 0 1-.8 .7 1.12 1.12 0 0 1-.3-1.1z"/>
<path d="M86.3 46.4l-.5 .6h.5zM86.3 46.1l.2-.1 .1 .1v.9l.2 .1a.15 .15 0 0 1-.1 .2 .15 .15 0 0 1-.1 0v.3h-.3v-.3h-.6l-.2-.1 .1-.3z"/>
<path d="M101 47.4l-.5 .6h.5zM100.9 47.2l.1-.2 .3 .1v.9l.2 .1a.16 .16 0 0 1 0 .2 .16 .16 0 0 1-.2 0v.2a.14 .14 0 0 1-.2 .2 .13 .13 0 0 1-.1-.2v-.2h-.7l-.1-.1 .1-.2z"/>
<path d="M107.5 47.4l-.3 .6h.5zM107.3 47.2a.25 .25 0 0 1 .3-.2 .25 .25 0 0 1 .1 .3l.5 1.1a.18 .18 0 0 1-.1 .3 .18 .18 0 0 1-.2-.2l-.1-.3h-.7v.3a.18 .18 0 0 1-.2 .2 .18 .18 0 0 1-.1-.3z"/>
<path d="M107.7 43.4v.4h.3v-.3a.16 .16 0 0 0-.2-.1 .16 .16 0 0 0-.1 0zM107.6 43.4a.25 .25 0 0 1 .3-.2 .25 .25 0 0 1 .2 .3l.3-.3v.1l-.3 .3v.2h.3v.1h-.8z"/>
<path d="M107.7 42.1v.1a.43 .43 0 0 0 .6 .1 .23 .23 0 0 0-.1-.3 .23 .23 0 0 0-.3 0zM107.6 42.1a.52 .52 0 0 1 .8 0 .39 .39 0 0 1-.6 .3l-.2-.1z"/>
<path d="M110.8 47.8v.2h.5a.25 .25 0 0 0-.2-.3 .25 .25 0 0 0-.3 .1zM110.6 47.6h.1a.54 .54 0 0 1 .6-.1 .54 .54 0 0 1 .3 .6h-.8a.34 .34 0 0 0 .3 .4 .34 .34 0 0 0 .3-.2 .13 .13 0 0 1 .2 .1 .13 .13 0 0 1-.1 .1 .63 .63 0 0 1-.9 0 .63 .63 0 0 1 0-.9z"/>
<path d="M114.8 48.2a.25 .25 0 0 0 .3 .2 .25 .25 0 0 0 .1-.3zM114.6 47.7a.6 .6 0 0 1 .8-.2 .6 .6 0 0 1 .2 .8 .18 .18 0 0 1 0 .3 .18 .18 0 0 1-.3 0v-.1a.44 .44 0 0 1-.5 .2 .44 .44 0 0 1-.3-.5 .54 .54 0 0 1 .6-.2l.2-.1a.28 .28 0 0 0-.3-.2 .28 .28 0 0 0-.3 .2h-.1l-.1-.1z"/>
<circle cx="99.9" cy="48.5" r=".15"/>
</g>
<g fill="none" stroke="#000" stroke-width=".25">
<circle cx="26.7" cy="1.2" r=".12"/>
<circle cx="62.2" cy="3.5" r="2.08"/>
<circle cx="66.5" cy="3.5" r="2.08"/>
</g>
<circle cx="78.3" cy="33.3" r=".21" fill="none" stroke="#000" stroke-width=".41"/>
</svg>
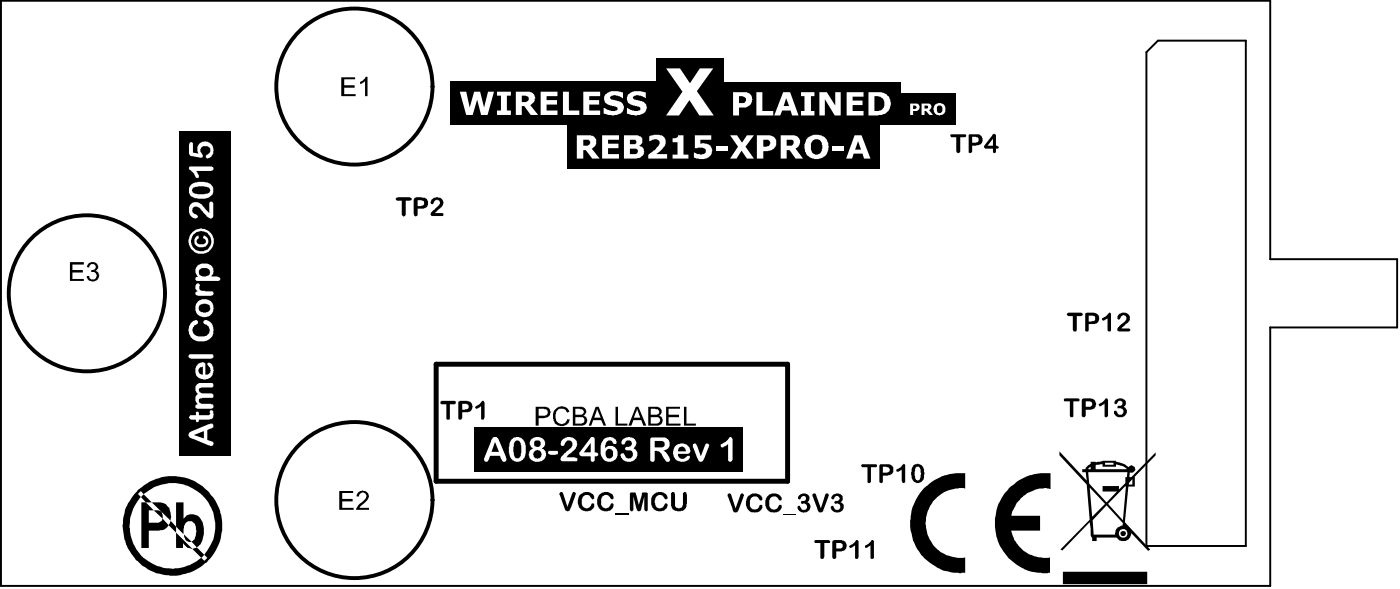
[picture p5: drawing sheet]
<svg xmlns="http://www.w3.org/2000/svg" width="119mm" height="50mm" viewBox="0 0 119 50" stroke-linecap="round" stroke-linejoin="round" font-family="sans-serif">
<path d="M.1 .1h108.1v21.9h10.8v5.9h-10.8v21.9h-108.1zM97.6 4.4l1-.9h7.5v42.9h-8.5z" fill="none" stroke="#000" stroke-width=".17"/>
<path d="M37.1 31h30v9.9h-30z" fill="none" stroke="#000" stroke-width=".42"/>
<g fill="#000">
<path d="M47.2 34.9a.71 .71 0 0 1 .7-.4 .71 .71 0 0 1 .6 .5l-.2 .1a.51 .51 0 0 0-.6-.3 .51 .51 0 0 0-.4 .6 .52 .52 0 0 0 .4 .6 .52 .52 0 0 0 .6-.3h.2a.75 .75 0 0 1-.9 .5 .75 .75 0 0 1-.5-.9zM52.4 34.6h.2v1.4h.8v.2h-1zM56.7 34.6h1.2v.2h-1v.5h.9v.2h-.9v.5h1.1v.2h-1.3zM58.3 34.6h.2v1.4h.8v.2h-1z"/>
<path d="M45.9 34.8v.6h.4a.3 .3 0 0 0 .3-.3 .3 .3 0 0 0-.3-.3zM45.6 34.6h.7a.5 .5 0 0 1 .6 .5 .5 .5 0 0 1-.6 .5h-.4v.6h-.3z"/>
<path d="M49 34.8v.5h.4a.26 .26 0 0 0 .3-.3 .26 .26 0 0 0-.3-.2zM49 35.5v.5h.5a.28 .28 0 0 0 .3-.3 .28 .28 0 0 0-.4-.2zM48.8 34.6h.6a.4 .4 0 0 1 .5 .3 .4 .4 0 0 1-.2 .5 .45 .45 0 0 1 .3 .5 .45 .45 0 0 1-.6 .3h-.6z"/>
<path d="M50.9 34.8l-.3 .7h.6zM50.7 34.6h.3l.6 1.6h-.2l-.2-.5h-.7l-.1 .5h-.3z"/>
<path d="M54.2 34.8l-.2 .7h.5zM54.2 34.6h.2l.6 1.6h-.2l-.2-.5h-.7l-.1 .5h-.3z"/>
<path d="M55.4 34.8v.5h.4a.26 .26 0 0 0 .3-.3 .26 .26 0 0 0-.3-.2zM55.4 35.5v.5h.5a.28 .28 0 0 0 .3-.3 .28 .28 0 0 0-.4-.2zM55.2 34.6h.7a.41 .41 0 0 1 .4 .3 .41 .41 0 0 1-.2 .5 .45 .45 0 0 1 .3 .5 .45 .45 0 0 1-.6 .3h-.6z"/>
</g>
<path d="M40.4 36.3h22.8v3.8h-22.8z" fill-rule="evenodd" fill="#000"/>
<g fill="#fff">
<path d="M46.7 38.3h.7a.17 .17 0 0 1 .1 .2 .17 .17 0 0 1-.2 .2l-.5-.1a.17 .17 0 0 1-.1-.1 .17 .17 0 0 1 0-.2z"/>
<path d="M47.9 37.4l.1-.1a.68 .68 0 0 1 .8-.1 .68 .68 0 0 1 .3 .7l-.1 .2-.8 .8h.8a.15 .15 0 0 1 .2 .2 .15 .15 0 0 1-.2 .1h-1.1a.24 .24 0 0 1-.2-.2 .24 .24 0 0 1 .2-.2l.5-.5a.4 .4 0 0 0 .4-.5 .4 .4 0 0 0-.5-.3l-.2 .2a.2 .2 0 0 1-.1 .2 .2 .2 0 0 1-.3-.2z"/>
<path d="M53 37.4l.3-.2h.3a.52 .52 0 0 1 .6 .3 .52 .52 0 0 1-.3 .6 .62 .62 0 0 1 .3 .8 .62 .62 0 0 1-.7 .4h-.1a.66 .66 0 0 1-.6-.7 .24 .24 0 0 1 .3 0 .24 .24 0 0 1 .2 .3 .36 .36 0 0 0 .5 0 .36 .36 0 0 0 0-.5 .36 .36 0 0 0-.4-.1 .18 .18 0 0 1-.1-.3 .18 .18 0 0 1 .3 0 .3 .3 0 0 0 .2-.3 .3 .3 0 0 0-.3-.3 .3 .3 0 0 0-.3 .3 .19 .19 0 0 1-.3 0 .19 .19 0 0 1 .1-.3z"/>
<path d="M59 37.8a.22 .22 0 0 1 .3 0 .22 .22 0 0 1 .1 .2l.3 .8 .3-.9a.19 .19 0 0 1 .2-.2 .19 .19 0 0 1 .2 .2l-.4 1.1a.29 .29 0 0 1-.2 .2 .29 .29 0 0 1-.3-.1l-.5-1z"/>
<path d="M61.4 37.8l.4-.2 .3-.4a.17 .17 0 0 1 .2 0 .17 .17 0 0 1 .1 .1v1.7a.2 .2 0 0 1-.1 .3 .2 .2 0 0 1-.3-.2v-1.3l-.4 .2a.17 .17 0 0 1-.2 0 .17 .17 0 0 1 0-.2z"/>
<path d="M42.2 37.6l-.3 .8h.6zM41.9 37.3a.37 .37 0 0 1 .4-.1 .37 .37 0 0 1 .2 .3l.6 1.4a.24 .24 0 0 1 0 .3 .24 .24 0 0 1-.4-.1l-.1-.3h-.9v.3a.22 .22 0 0 1-.3 .2 .22 .22 0 0 1-.2-.3z"/>
<path d="M43.8 37.5l-.1 .7a.78 .78 0 0 0 .2 .7 .3 .3 0 0 0 .4 0 .3 .3 0 0 0 .1-.3v-.4a.59 .59 0 0 0-.4-.7zM43.6 37.4a.74 .74 0 0 1 .8-.1 .74 .74 0 0 1 .4 .8v.2a.84 .84 0 0 1-.6 1 .89 .89 0 0 1-.9-1.2l.1-.4z"/>
<path d="M45.5 37.7a.28 .28 0 0 0 .5 0 .28 .28 0 0 0-.5 0zM45.5 38.4a.37 .37 0 0 0 0 .5 .37 .37 0 0 0 .5 0 .36 .36 0 0 0 0-.6 .36 .36 0 0 0-.5 .1zM45.2 37.4a.68 .68 0 0 1 .8-.2 .68 .68 0 0 1 .4 .6l-.3 .3a.61 .61 0 0 1 .3 .8 .61 .61 0 0 1-.7 .4 .6 .6 0 0 1-.6-.5 .6 .6 0 0 1 .3-.7 .56 .56 0 0 1-.2-.7z"/>
<path d="M50.3 37.7l-.6 .8h.6zM50.3 37.3l.2-.1 .2 .1v1.2a.19 .19 0 0 1 .2 .2 .19 .19 0 0 1-.2 .1v.3a.17 .17 0 0 1-.2 .2 .17 .17 0 0 1-.2-.2v-.3h-.7a.24 .24 0 0 1-.3-.2 .24 .24 0 0 1 .2-.3z"/>
<path d="M51.4 37.4a.64 .64 0 0 1 .6-.2 .64 .64 0 0 1 .5 .4v.2h-.2a.34 .34 0 0 0-.4-.3 .34 .34 0 0 0-.3 .3l-.1 .3a.67 .67 0 0 1 1.1 .4 .67 .67 0 0 1-.8 .8 .96 .96 0 0 1-.6-1.2v-.4zM51.7 38.3a.49 .49 0 0 0 .2 .7 .42 .42 0 0 0 .3-.5 .42 .42 0 0 0-.5-.3z"/>
<path d="M55.8 37.5v.6h.4a.3 .3 0 0 0 .4-.3 .3 .3 0 0 0-.4-.3zM55.4 37.3l.1-.1h.9a.57 .57 0 0 1 .6 .5 .57 .57 0 0 1-.5 .6l.4 .4a.49 .49 0 0 1 .1 .6h-.2l-.4-.7-.4-.3h-.2v.7a.2 .2 0 0 1-.2 .3 .2 .2 0 0 1-.2-.3z"/>
<path d="M57.8 38.1l-.1 .3h.7a.35 .35 0 0 0-.2-.4 .35 .35 0 0 0-.4 .1zM57.5 38a.72 .72 0 0 1 .8-.3 .72 .72 0 0 1 .5 .8l-.2 .1h-.9a.4 .4 0 0 0 .3 .4 .4 .4 0 0 0 .5-.2h.1a.17 .17 0 0 1 .2 .1 .17 .17 0 0 1-.2 .2l-.3 .1a.8 .8 0 0 1-.8-.3 .8 .8 0 0 1 0-.9z"/>
</g>
<g fill="#000">
<path d="M47.7 41.9a.16 .16 0 0 1 .2 0 .16 .16 0 0 1 .1 .2l.3 1 .4-1a.17 .17 0 0 1 .2-.2 .17 .17 0 0 1 .1 .2l-.4 1.1a.3 .3 0 0 1-.4 .2h-.1zM49.3 42.1h.1a.71 .71 0 0 1 1.2 .2 .17 .17 0 0 1-.2 .1 .17 .17 0 0 1-.1-.2 .47 .47 0 0 0-.6 0 .47 .47 0 0 0-.1 .6 .42 .42 0 0 0 .4 .4 .42 .42 0 0 0 .4-.4 .26 .26 0 0 1 .2 .2 .26 .26 0 0 1-.2 .3 .76 .76 0 0 1-1 0 .76 .76 0 0 1-.1-1zM51 42.1a.73 .73 0 0 1 1.3 .2l-.1 .2-.2-.1a.44 .44 0 0 0-.6-.2 .44 .44 0 0 0-.2 .6 .42 .42 0 0 0 .4 .4 .42 .42 0 0 0 .4-.4 .23 .23 0 0 1 .3 .2 .23 .23 0 0 1-.1 .2 .8 .8 0 0 1-1.1 .1 .8 .8 0 0 1-.2-1.1zM52.4 43.6h1.1v.1h-1.1zM53.7 41.9h.5l.2 1 .3-1h.5v1.5a.15 .15 0 0 1-.2 .1 .15 .15 0 0 1-.1-.2v-1.1l-.3 1a.22 .22 0 0 1-.2 .3 .22 .22 0 0 1-.2-.3l-.3-1v1.2l-.2 .1-.1-.1zM55.6 42.2a.71 .71 0 0 1 .7-.4 .71 .71 0 0 1 .6 .6h-.1a.13 .13 0 0 1-.1 .1 .13 .13 0 0 1-.1-.2 .45 .45 0 0 0-.6-.1 .45 .45 0 0 0-.2 .5 .45 .45 0 0 0 .3 .5 .45 .45 0 0 0 .5-.4 .26 .26 0 0 1 .3 .3 .26 .26 0 0 1-.3 .2 .78 .78 0 0 1-.9 0 .78 .78 0 0 1-.2-1zM57.2 41.9v-.1l.3 .1v.9a.35 .35 0 0 0 .3 .4 .35 .35 0 0 0 .4-.4v-.7a.17 .17 0 0 1 .1-.3 .18 .18 0 0 1 .2 .3v.8a.66 .66 0 0 1-.6 .6 .66 .66 0 0 1-.7-.5zM62 42.1v-.1a.19 .19 0 0 1 .2 0 .19 .19 0 0 1 .1 .2l.3 1 .4-1a.18 .18 0 0 1 .2-.2 .18 .18 0 0 1 .1 .3l-.4 1a.28 .28 0 0 1-.2 .3 .28 .28 0 0 1-.3-.2zM63.7 42.3a.7 .7 0 0 1 .7-.3 .7 .7 0 0 1 .5 .5v.1h-.2a.44 .44 0 0 0-.5-.4 .44 .44 0 0 0-.3 .6 .43 .43 0 0 0 .3 .5 .43 .43 0 0 0 .5-.4 .22 .22 0 0 1 .2 .2 .22 .22 0 0 1-.1 .3 .77 .77 0 0 1-1 0 .77 .77 0 0 1-.2-1zM65.3 42.3a.72 .72 0 0 1 1.3 .1l-.1 .2h-.1a.46 .46 0 0 0-.6-.3 .46 .46 0 0 0-.3 .6 .4 .4 0 0 0 .4 .4 .4 .4 0 0 0 .4-.3l.1-.1a.22 .22 0 0 1 .2 .2 .22 .22 0 0 1-.2 .3 .74 .74 0 0 1-1.2-.4v-.4zM66.7 43.7h1.1v.1h-1.1zM68 42.2h.1a.45 .45 0 0 1 .6-.2 .45 .45 0 0 1 .1 .7 .52 .52 0 0 1 0 .8 .52 .52 0 0 1-.8-.1 .16 .16 0 0 1-.1-.3 .16 .16 0 0 1 .2 0 .29 .29 0 0 0 .4 .2 .29 .29 0 0 0 .1-.4l-.1-.1a.15 .15 0 0 1-.2 0 .15 .15 0 0 1 0-.2 .15 .15 0 0 1 .2 0 .21 .21 0 0 0 .1-.4 .21 .21 0 0 0-.4 .1 .15 .15 0 0 1-.2 .1 .15 .15 0 0 1 0-.2z"/>
<path d="M69.2 42.1l.1-.1h.2l.4 1.2 .4-1a.18 .18 0 0 1 .2-.2 .18 .18 0 0 1 0 .3l-.4 1a.23 .23 0 0 1-.2 .3 .23 .23 0 0 1-.2-.2zM70.8 42.2l.2-.1a.45 .45 0 0 1 .6 0 .45 .45 0 0 1 0 .6 .51 .51 0 0 1 .1 .7 .51 .51 0 0 1-.7 .1 .23 .23 0 0 1-.2-.2 .23 .23 0 0 1 .2-.3v.1a.3 .3 0 0 0 .4 .3 .3 .3 0 0 0 .1-.5l-.2-.1a.14 .14 0 0 1-.2 0 .14 .14 0 0 1 .1-.2 .22 .22 0 0 0 .3-.2 .22 .22 0 0 0-.2-.2 .22 .22 0 0 0-.2 .2 .15 .15 0 0 1-.3 0 .15 .15 0 0 1 0-.2z"/>
<path d="M94.1 39.4v.1h.7v-.1zM93.3 39.6v.3h2.7a1.43 1.43 0 0 0-1-.4v.2h-1.1v-.2zM92.7 39.9h.2v-.2zM96.4 40.7l-.3 .4v.1h.3zM92.7 40.2l.1 .9 1.4 1.6 .9-.9h-1.2v-.5h1.4v.3l.6-.5v-.5h.1v-.4zM92.8 41.5l.2 2.5 1.1-1.1zM95.9 41.3l-1.5 1.6 1.2 1.3zM94.2 43l-1.1 1.2v1.3h1.9a.59 .59 0 0 1 .6-.8v-.2zM95.5 45.4a.22 .22 0 0 1 .4 0 .22 .22 0 0 1-.4 0zM95.3 45.4a.37 .37 0 0 0 .7 0 .37 .37 0 0 0-.7 0zM90.2 38.4l2.4 2.5-.1-.7h-.3v-.3h.2l.5-.5v-.1h.5l.5-.1h1.1v.1l.9 .3a.32 .32 0 0 0 .5 0 .32 .32 0 0 1 .3 .4 .32 .32 0 0 1-.5 .2v.4h.2l2-2.1v.2l-1.7 1.8v.9h-.6l-.3 3 2.2 2.3-.2 .2-1.5-1.6a.66 .66 0 0 1-.4 .7 .66 .66 0 0 1-.8-.3h-1.7v.3h-.4v-.3l-.1-.1-.1-1.2-2.3 2.4-.2-.1 2.5-2.5-.2-3-2.4-2.5zM90.5 48.6h7.2v1.1h-7.2z"/>
<path d="M11.7 42l.3 .3 .3-.2 .6 .6h.4a1.1 1.1 0 0 1 1.2 1.4v.2l-1.6-1.6h-.5l-.4-.4a3.7 3.7 0 0 0 .1 5 3.7 3.7 0 0 0 5.1 .1l.2 .3 .3-.3-.3-.2-.2 .2-.8-.7-.5-.1-.3-.4v.4h-.6v-1.3l1.4 1.4 .4-.1 .6 .6a3.6 3.6 0 0 0-.1-5 3.6 3.6 0 0 0-5-.1l-.3-.3zM12 42.7h.4l.7 .7h.3a.51 .51 0 0 1 .5 .7l-.8-.7h-.4v1.1h.8l.4-.4 .5 .6 .1-.4 .5 .5v-2.1h.6v1.4a.94 .94 0 0 1 1.1-.3 .94 .94 0 0 1 .6 .9l.1 .6a1.48 1.48 0 0 1-.6 1.3l-.5-.5a.54 .54 0 0 1-.7-.7l.7 .7a1.11 1.11 0 0 0 .3-1.4 .49 .49 0 0 0-.5-.4 .49 .49 0 0 0-.4 .6l-.1 .5-.6-.6v.5l-.6-.6-.1 .1a1.11 1.11 0 0 1-1 .3h-.6v1.5h-.7zM10.4 44.7a4.2 4.2 0 0 1 8.5 0 4.2 4.2 0 0 1-8.5 0z"/>
<path d="M78.7 41.5h.1a4 4 0 0 1 3.4-1.3v1.3a2.98 2.98 0 0 0-3.2 1.9 2.94 2.94 0 0 0 3.2 4v1.3a4.3 4.3 0 0 1-4.3-2.4 4.3 4.3 0 0 1 .8-4.8zM86 41.5a4.3 4.3 0 0 1 3.5-1.3v1.4a2.95 2.95 0 0 0-3.4 2.3h2.5v1.2h-2.5a2.84 2.84 0 0 0 3.3 2.3v1.3a4.2 4.2 0 0 1-4.3-2.4 4.2 4.2 0 0 1 .9-4.8z"/>
</g>
<path d="M15.3 11.2h4.3v27.5h-4.3z" fill-rule="evenodd" fill="#000"/>
<g fill="#fff">
<path d="M16.1 35.4l.1-.1h.5v-.2a.15 .15 0 0 1 .2-.1 .15 .15 0 0 1 0 .2v.1h.8a.17 .17 0 0 0 .2-.1 .17 .17 0 0 0 0-.1 .17 .17 0 0 1 .2-.2 .17 .17 0 0 1 .1 .3v.1a.44 .44 0 0 1-.5 .4h-.8a.14 .14 0 0 1-.1 .2 .14 .14 0 0 1-.1-.2h-.5l-.1-.2z"/>
<path d="M16.7 32.8l.2-.2h1.1a.2 .2 0 0 1 .2 .2 .2 .2 0 0 1-.2 .2h-.7a.28 .28 0 0 0-.4 .2 .28 .28 0 0 0 .4 .3h.7a.2 .2 0 0 1 .2 .1 .2 .2 0 0 1-.2 .2h-.7a.29 .29 0 0 0-.3 .1 .29 .29 0 0 0 0 .4h.2h.8a.21 .21 0 0 1 .2 .3 .21 .21 0 0 1-.2 .2h-1.1a.19 .19 0 0 1-.3-.2 .19 .19 0 0 1 .3-.2 .66 .66 0 0 1-.1-.9 .58 .58 0 0 1-.1-.7z"/>
<path d="M16.1 30.2l1.9-.1a.2 .2 0 0 1 .2 .2 .2 .2 0 0 1-.2 .2h-1.7l-.2-.1z"/>
<path d="M16.2 27.5a.47 .47 0 0 1 .7-.2v.2a.55 .55 0 0 0-.5 .5 .55 .55 0 0 0 .3 .5l.2 .1a.71 .71 0 0 0 1-.5 .78 .78 0 0 0-.6-.6 .27 .27 0 0 1 .2-.3 .27 .27 0 0 1 .3 .1h.1a1.01 1.01 0 0 1 .1 1.3 1.01 1.01 0 0 1-1.1 .4 1.01 1.01 0 0 1-.7-1.5z"/>
<path d="M16.7 24.2a.19 .19 0 0 1 .3 0 .19 .19 0 0 1 0 .2 .33 .33 0 0 0 .4 .3l.6 .1a.2 .2 0 0 1 .2 .2 .2 .2 0 0 1-.2 .2h-1.1a.19 .19 0 0 1-.3-.2 .19 .19 0 0 1 .3-.2 .42 .42 0 0 1-.2-.6z"/>
<path d="M16.3 17.3a.82 .82 0 0 1 1.1 .4l.4 .4v-.9h.3l.1 .1v1.1a.27 .27 0 0 1-.3 .2 .27 .27 0 0 1-.2-.2l-.5-.5a.41 .41 0 0 0-.5-.3 .41 .41 0 0 0-.4 .3l.3 .3a.2 .2 0 0 1 .2 .2 .2 .2 0 0 1-.3 .1h-.1a.86 .86 0 0 1-.1-1.2z"/>
<path d="M16.1 14.2h1.8a.2 .2 0 0 1 .3 .1 .2 .2 0 0 1-.2 .2h-1.3l.2 .3a.18 .18 0 0 1 .1 .2 .18 .18 0 0 1-.3 .1 .18 .18 0 0 1-.1-.2l-.4-.4a.17 .17 0 0 1-.1-.2 .17 .17 0 0 1 0-.1z"/>
<path d="M16.1 12.1h.1a.15 .15 0 0 1 .2 0 .15 .15 0 0 1 0 .2v.7h.5a.69 .69 0 0 1 .6-1 .69 .69 0 0 1 .7 .9 .5 .5 0 0 1-.6 .5v-.2a.4 .4 0 0 0 .3-.5 .4 .4 0 0 0-.5-.3 .4 .4 0 0 0-.2 .6v.1a.19 .19 0 0 1 .1 .2 .19 .19 0 0 1-.3 .1l-.9-.2z"/>
<path d="M16.5 37l.9 .3v-.6zM16.1 36.8l.2-.1 1.5-.6a.22 .22 0 0 1 .4 .1 .22 .22 0 0 1-.3 .3l-.2 .1v.8l.2 .1a.24 .24 0 0 1 .3 .3 .24 .24 0 0 1-.4 .1l-1.3-.6a.35 .35 0 0 1-.4-.1 .35 .35 0 0 1 0-.4z"/>
<path d="M16.9 31.4a.34 .34 0 0 0 .1 .3 .34 .34 0 0 0 .3 .2v-.7zM16.7 31.1a.52 .52 0 0 1 .8-.2v1a.42 .42 0 0 0 .4-.4 .42 .42 0 0 0-.2-.4v-.1a.19 .19 0 0 1 .1-.2 .19 .19 0 0 1 .2 .2l.1 .1a.78 .78 0 0 1-.7 1.2 .78 .78 0 0 1-.7-1.2z"/>
<path d="M17 25.9a.4 .4 0 0 0 0 .5 .4 .4 0 0 0 .4 .2 .39 .39 0 0 0 .5-.4 .39 .39 0 0 0-.5-.4zM16.6 26.2a.8 .8 0 0 1 1.6 0 .8 .8 0 0 1-1.6 0z"/>
<path d="M16.8 22.6a.84 .84 0 0 1 1.4 .3 .49 .49 0 0 1-.3 .6l.6 .1a.18 .18 0 0 1 .3 .2 .18 .18 0 0 1-.3 .1h-1.6a.19 .19 0 0 1-.3-.2 .19 .19 0 0 1 .3-.2 .66 .66 0 0 1-.1-.9zM17 22.9a.42 .42 0 0 0 0 .5 .42 .42 0 0 0 .5 .1 .38 .38 0 0 0 .4-.5 .38 .38 0 0 0-.6-.2z"/>
<path d="M16.6 20.2l.3-.2v.3a.29 .29 0 0 0-.1 .4 .29 .29 0 0 0 .4 .1 .25 .25 0 0 0 .3-.3 .25 .25 0 0 0-.2-.2l.1-.3a.54 .54 0 0 1 .3 .8 .54 .54 0 0 1-.8 .2 .51 .51 0 0 1-.3-.8zM16.3 20.5a.86 .86 0 0 0 1.7 0 .86 .86 0 0 0-1.7 0zM16.1 20.5a1.08 1.08 0 0 1 2.1 0 1.08 1.08 0 0 1-2.1 0z"/>
<path d="M16.4 16a.37 .37 0 0 0 .1 .4 .37 .37 0 0 0 .4 .1h.3a.67 .67 0 0 0 .7-.2 .39 .39 0 0 0-.5-.5h-.5zM16.2 15.8l.1-.1a1.53 1.53 0 0 1 1.7 .1 .76 .76 0 0 1 0 .8 .76 .76 0 0 1-.8 .3h-.3a.73 .73 0 0 1-.7-.3 .73 .73 0 0 1 0-.8z"/>
</g>
<path d="M76.7 7.9h4.7v2.7h-4.7z" fill-rule="evenodd" fill="#000"/>
<g fill="#fff">
<path d="M77.8 9v.3a.19 .19 0 0 0 .2-.1 .19 .19 0 0 0 0-.2 .19 .19 0 0 0-.2 0zM77.5 8.8h.4a.33 .33 0 0 1 .4 .4 .33 .33 0 0 1-.4 .2h-.1v.4h-.3z"/>
<path d="M78.7 9v.2h.3v-.2zM78.5 8.8h.5a.29 .29 0 0 1 .3 .2 .29 .29 0 0 1-.2 .4l.4 .4h-.3l-.3-.4h-.2v.4h-.2z"/>
<path d="M79.8 9a.35 .35 0 0 0 0 .4 .35 .35 0 0 0 .3 .2 .35 .35 0 0 0 .2-.4 .35 .35 0 0 0-.4-.2zM79.5 9.3a.55 .55 0 0 1 1.1 0 .55 .55 0 0 1-1.1 0z"/>
</g>
<path d="M48.3 10.6h26.7v3.7h-26.7z" fill-rule="evenodd" fill="#000"/>
<g fill="#fff">
<path d="M51.3 11.5h1.4v.4h-.9v.3h.9v.4h-.9v.5h.9v.4h-1.4z"/>
<path d="M55.3 11.6l.3-.1a.71 .71 0 0 1 1.1 .6 1.53 1.53 0 0 1-.8 1h.9v.4h-1.6v-.4l.6-.4a.79 .79 0 0 0 .3-.7 .62 .62 0 0 0-.8 0z"/>
<path d="M57.3 11.8l.4-.1v-.2h.5v1.6h.4v.4h-1.3v-.4h.4v-1h-.4z"/>
<path d="M59.2 11.5h1.4v.4h-1v.3h.4a.68 .68 0 0 1 .6 .8 .68 .68 0 0 1-.8 .5l-.7-.1v-.4l.5 .1a.37 .37 0 0 0 .4 0 .37 .37 0 0 0 .1-.4 .99 .99 0 0 0-.9-.1z"/>
<path d="M61 12.4h1v.4h-1z"/>
<path d="M62.2 11.5h.6l.4 .6 .4-.6h.6l-.7 1 .7 1h-.6l-.4-.7-.5 .7h-.5l.7-1z"/>
<path d="M70.8 12.4h1.1v.4h-1.1z"/>
<path d="M49.7 11.9v.5h.2a.28 .28 0 0 0 .4-.3 .28 .28 0 0 0-.4-.2zM49.1 11.5h1a.59 .59 0 0 1 .7 .4 .59 .59 0 0 1-.4 .7l.7 .9h-.7l-.5-.7h-.2v.7h-.6z"/>
<path d="M53.6 11.9v.4h.3a.22 .22 0 0 0 .3-.2 .22 .22 0 0 0-.3-.2zM53.6 12.6v.5h.4a.25 .25 0 0 0 .3-.3 .25 .25 0 0 0-.4-.2zM53.1 11.5h.9a.53 .53 0 0 1 .5 .1 .53 .53 0 0 1 .2 .5l-.2 .3a.57 .57 0 0 1 .3 .7 .57 .57 0 0 1-.6 .4h-1.1z"/>
<path d="M65 11.9v.6h.2a.31 .31 0 0 0 .4-.3 .31 .31 0 0 0-.4-.3zM64.5 11.5h.9a.68 .68 0 0 1 .7 .7 .68 .68 0 0 1-.8 .7h-.3v.6h-.5z"/>
<path d="M67 11.9v.5h.2a.27 .27 0 0 0 .4-.2 .27 .27 0 0 0-.3-.3zM66.5 11.5h1a.59 .59 0 0 1 .6 .4 .59 .59 0 0 1-.3 .7l.6 .9h-.6l-.5-.7h-.3v.7h-.5z"/>
<path d="M69.2 12l-.1 .2v.3a.5 .5 0 0 0 .4 .7 .5 .5 0 0 0 .5-.6 .6 .6 0 0 0-.5-.8zM68.8 11.7a1.1 1.1 0 0 1 1.7 .5v.1a1.05 1.05 0 0 1-1.2 1.2 1.05 1.05 0 0 1-.7-1.6z"/>
<path d="M73.1 12l-.3 .7h.5zM72.8 11.5h.6l.7 2h-.5l-.1-.4h-.8l-.1 .4h-.5z"/>
</g>
<path d="M38.4 6.9h17.5v3.7h-17.5z" fill-rule="evenodd" fill="#000"/>
<g fill="#fff">
<path d="M39.2 7.8h.5l.3 1.3 .4-1.3h.5l.3 1.3 .4-1.3h.5l-.6 2h-.5l-.4-1.3-.3 1.3h-.6z"/>
<path d="M42.3 7.8h1.2v.3h-.3v1.3h.3v.4h-1.2v-.4h.4v-1.3h-.4z"/>
<path d="M46 7.8h1.5v.4h-.9v.3h.8v.4h-.8v.5h.9v.4h-1.5z"/>
<path d="M47.9 7.8h.6v1.6h.8v.4h-1.4z"/>
<path d="M49.7 7.8h1.4v.4h-.9v.3h.8v.4h-.8v.5h.9v.4h-1.4z"/>
<path d="M51.5 8.1l.1-.1a1.51 1.51 0 0 1 1.5-.1v.4h-.2a.66 .66 0 0 0-.9 0l.1 .2 .4 .1a.62 .62 0 0 1 .6 .7 .62 .62 0 0 1-.8 .5h-.6l-.3-.1v-.5l.5 .2a.75 .75 0 0 0 .7-.1v-.2l-.4-.1a.68 .68 0 0 1-.7-.8z"/>
<path d="M53.5 8.1v-.1a1.51 1.51 0 0 1 1.5-.1v.4a.72 .72 0 0 0-1.1 0l.1 .2h.3a.77 .77 0 0 1 .8 .7 .83 .83 0 0 1-.9 .6l-.8-.1v-.5h.1a1.02 1.02 0 0 0 1 .1 .34 .34 0 0 0-.4-.3 .72 .72 0 0 1-.7-.7z"/>
<path d="M44.4 8.1v.6h.3a.29 .29 0 0 0 .3-.2 .29 .29 0 0 0-.1-.3zM43.9 7.8h.9a.59 .59 0 0 1 .8 .4 .59 .59 0 0 1-.4 .7l.6 .9h-.6l-.5-.8h-.3v.8h-.5z"/>
</g>
<path d="M61.6 7h15.1v3.6h-15.1z" fill-rule="evenodd" fill="#000"/>
<g fill="#fff">
<path d="M64.4 7.8h.5v1.6h1v.4h-1.5z"/>
<path d="M68.2 7.8h1.2v.4h-.3v1.2h.3v.4h-1.2v-.4h.3v-1.2h-.3z"/>
<path d="M69.8 7.8h.6l.7 1.2v-1.2h.5v2h-.5l-.8-1.4v1.4h-.5z"/>
<path d="M72.1 7.8h1.4v.4h-.9v.4h.9v.3h-.9v.5h.9v.4h-1.4z"/>
<path d="M62.9 8.2v.6h.2a.31 .31 0 0 0 .4-.3 .31 .31 0 0 0-.4-.3zM62.4 7.8h1a.65 .65 0 0 1 .7 .7 .65 .65 0 0 1-.6 .6h-.6v.7h-.5z"/>
<path d="M67 8.3l-.3 .7h.5zM66.7 7.8h.6l.7 2h-.5l-.2-.4h-.7l-.2 .4h-.5z"/>
<path d="M74.5 8.2v1.2h.2a.63 .63 0 0 0 .6-.6 .63 .63 0 0 0-.6-.6zM74 7.8h.8a1 1 0 0 1 1.1 1.1 1 1 0 0 1-1.2 .9h-.7z"/>
</g>
<path d="M55.9 5h5.7v5.6h-5.7z" fill-rule="evenodd" fill="#000"/>
<path d="M56.7 5.8h1.2l.9 1.3 .8-1.3h1.1l-1.3 2 1.4 2h-1.2l-.9-1.3-.9 1.3h-1.1l1.4-2z" fill="#fff"/>
<g fill="#000">
<path d="M29.1 6.6h1.1v.1h-.9v.6h.9v.2h-.9v.5h1v.2h-1.2zM30.7 7l.2-.1 .2-.4h.2v1.7h-.2v-1.3l-.4 .3zM33.7 16.9l.2-.1h1a.14 .14 0 0 1 .2 .2 .13 .13 0 0 1-.2 .1h-.3v1.1a.17 .17 0 0 1-.2 .2 .17 .17 0 0 1-.2-.2v-1.1h-.4zM36.8 17l.1-.1a.5 .5 0 0 1 .6-.1 .5 .5 0 0 1 .2 .6v.1l-.7 .6h.7l.1 .2-1 .1a.4 .4 0 0 1 .2-.6l.1-.1a.42 .42 0 0 0 .2-.7 .36 .36 0 0 0-.4 .4l-.2-.1zM80.9 11.5l1.3-.1a.13 .13 0 0 1 .1 .2 .13 .13 0 0 1-.2 .1h-.3l-.1 1.3a.14 .14 0 0 1-.1 0 .14 .14 0 0 1-.1-.1l-.1-1.2h-.4zM6 22.3h1.1v.2h-.9v.5h.9v.2h-.9v.5h.9v.2h-1.1zM7.6 22.4a.45 .45 0 0 1 .6 0 .45 .45 0 0 1 0 .7 .5 .5 0 0 1 0 .8 .5 .5 0 0 1-.8-.2v-.2h.2a.34 .34 0 0 0 .4 .3 .34 .34 0 0 0 .2-.4 .34 .34 0 0 0-.4-.3v-.1a.27 .27 0 0 0 .3-.2 .27 .27 0 0 0-.2-.4 .27 .27 0 0 0-.3 .4l-.2-.1zM37.5 34.2l.1-.1h1.2l-.1 .3h-.4v1.3h-.3v-1.3h-.4l-.1-.1zM40.5 34.6l.3-.2 .3-.3a.09 .09 0 0 1 .1 0 .09 .09 0 0 1 0 .1l.1 1.3-.1 .2h-.2v-1.1l-.2 .1a.16 .16 0 0 1-.2 .1 .16 .16 0 0 1-.1-.2zM73.3 39.6l.1-.1h1.3l-.1 .2h-.4v1.2a.16 .16 0 0 1-.2 .2 .16 .16 0 0 1-.1-.2v-1.2h-.5zM76.3 39.9l.4-.1 .2-.3a.11 .11 0 0 1 .1-.1 .11 .11 0 0 1 .1 .2v1.3a.15 .15 0 0 1-.1 .2 .15 .15 0 0 1-.2-.2v-1l-.3 .2h-.1zM90.6 33.9h1.2l.2 .1-.1 .1h-.5v1.3l-.1 .1a.14 .14 0 0 1-.1 0 .14 .14 0 0 1-.1-.2v-1.2h-.4z"/>
<path d="M90.9 26.7l.1-.1h1.1l.1 .1v.1l-.1 .1h-.4v1.2l-.1 .1a.17 .17 0 0 1-.2 0 .17 .17 0 0 1 0-.2v-1.1h-.4l-.1-.1zM93.6 34.4l.5-.4a.15 .15 0 0 1 .1-.1 .15 .15 0 0 1 .2 .1v1.3a.15 .15 0 0 1-.2 .2 .15 .15 0 0 1-.1-.2v-1l-.2 .1a.17 .17 0 0 1-.2 .2 .17 .17 0 0 1-.1-.2zM93.9 27.1l.3-.2 .2-.2a.13 .13 0 0 1 .1-.1 .13 .13 0 0 1 .1 .2v1.2a.15 .15 0 0 1-.1 .2 .15 .15 0 0 1-.2-.2v-.9l-.2 .1a.14 .14 0 0 1-.2 .1 .14 .14 0 0 1 0-.2zM95 34a.52 .52 0 0 1 .5-.1 .52 .52 0 0 1 .4 .4l-.2 .3a.47 .47 0 0 1 .2 .7 .47 .47 0 0 1-.6 .2 .36 .36 0 0 1-.3-.2 .36 .36 0 0 1 0-.4 .45 .45 0 0 0 .6 .4 .33 .33 0 0 0 0-.5 .33 .33 0 0 0-.4-.1v-.2a.24 .24 0 0 0 .4-.2 .24 .24 0 0 0-.3-.2l-.1 .1a.17 .17 0 0 1-.1 .2 .17 .17 0 0 1-.2-.2 .17 .17 0 0 1 .1-.2zM95.2 26.8h.1a.53 .53 0 0 1 .8 0 .53 .53 0 0 1-.2 .8l-.4 .3h.7l.1 .1-.1 .2h-.9l-.1-.1a.67 .67 0 0 1 .4-.6l.1-.1a.33 .33 0 0 0 .2-.3 .33 .33 0 0 0-.3-.3l-.2 .3a.16 .16 0 0 1-.2 0 .16 .16 0 0 1 0-.3zM28.9 41.8h1.2v.1h-1v.5h.9v.2h-.9v.6h1v.2h-1.2zM30.5 41.9a.51 .51 0 0 1 .6-.1 .51 .51 0 0 1 .2 .6l-.7 .8h.8v.2h-1.1l.2-.4 .4-.3a.58 .58 0 0 0 .2-.7 .33 .33 0 0 0-.3-.1 .33 .33 0 0 0-.2 .3h-.2zM69.4 46l1.2-.1a.13 .13 0 0 1 .1 .2 .13 .13 0 0 1-.2 .1h-.3v1.2l-.1 .1a.14 .14 0 0 1-.2 0 .14 .14 0 0 1 0-.1v-1.2h-.5zM72.3 46.4l.5-.3a.15 .15 0 0 1 .2-.2 .15 .15 0 0 1 .1 .2v1.3a.15 .15 0 0 1-.1 .1 .15 .15 0 0 1-.2-.1v-1l-.2 .2a.15 .15 0 0 1-.2 0 .15 .15 0 0 1-.1-.2zM73.7 46.4l.3-.1 .1-.2a.15 .15 0 0 1 .2-.2 .15 .15 0 0 1 .1 .2v1.3a.15 .15 0 0 1-.1 .1 .15 .15 0 0 1-.2-.1v-1l-.2 .1a.14 .14 0 0 1-.2 .1 .14 .14 0 0 1 0-.2z"/>
<path d="M35.6 17v.5h.2a.26 .26 0 0 0 .3-.2 .26 .26 0 0 0-.3-.3zM35.3 16.9l.1-.1h.5a.47 .47 0 0 1 .6 .5 .47 .47 0 0 1-.6 .4h-.3l-.1 .6a.16 .16 0 0 1-.2 .1 .16 .16 0 0 1-.1-.2z"/>
<path d="M82.8 11.6v.5h.3a.26 .26 0 0 0 .2-.2 .26 .26 0 0 0-.2-.3zM82.5 11.5l.6-.1a.49 .49 0 0 1 .6 .5 .49 .49 0 0 1-.6 .5h-.3v.6a.16 .16 0 0 1-.2 0 .16 .16 0 0 1-.1-.2z"/>
<path d="M84.6 11.8l-.5 .6h.5zM84.5 11.5a.15 .15 0 0 1 .2-.1 .15 .15 0 0 1 .1 .2v.8h.2a.11 .11 0 0 1 .1 .1 .11 .11 0 0 1-.1 .1h-.2v.3a.13 .13 0 0 1-.1 .1 .13 .13 0 0 1-.1-.1v-.3h-.7h-.1v-.2z"/>
<path d="M39.4 34.3v.5h.2a.26 .26 0 0 0 .3-.2 .26 .26 0 0 0-.3-.3zM39 34.2l.2-.1h.5a.49 .49 0 0 1 .6 .5 .49 .49 0 0 1-.6 .5h-.3v.4a.17 .17 0 0 1-.2 .2 .17 .17 0 0 1-.2-.2z"/>
<path d="M75.2 39.7v.5h.2a.26 .26 0 0 0 .4-.3 .26 .26 0 0 0-.4-.2zM74.9 39.6l.1-.1h.5a.49 .49 0 0 1 .6 .5 .49 .49 0 0 1-.6 .5h-.3v.4a.15 .15 0 0 1-.2 .2 .15 .15 0 0 1-.1-.2z"/>
<path d="M78 39.8l-.1 .4a.64 .64 0 0 0 .3 .7 .54 .54 0 0 0 .2-.7 .3 .3 0 0 0 0-.4 .3 .3 0 0 0-.4-.1zM77.8 39.6a.56 .56 0 0 1 .6-.1 .56 .56 0 0 1 .3 .7 .68 .68 0 0 1-.5 .9 .75 .75 0 0 1-.6-1v-.2z"/>
<path d="M92.5 34.1v.5h.2a.24 .24 0 0 0 .3-.2 .24 .24 0 0 0-.3-.3zM92.2 33.9h.6a.49 .49 0 0 1 .6 .5 .49 .49 0 0 1-.6 .4h-.3v.6l-.1 .1-.3-.1z"/>
<path d="M92.7 26.8v.5h.3a.24 .24 0 0 0 .3-.2 .24 .24 0 0 0-.3-.3zM92.4 26.7l.2-.1h.6a.49 .49 0 0 1 .4 .6 .49 .49 0 0 1-.6 .4h-.3v.4a.15 .15 0 0 1-.1 .2 .15 .15 0 0 1-.2-.2z"/>
<path d="M71.2 46.2v.4h.2a.24 .24 0 0 0 .4-.2 .24 .24 0 0 0-.3-.2zM70.9 46l.7-.1a.49 .49 0 0 1 .5 .5 .49 .49 0 0 1-.6 .5h-.3v.5l-.1 .1a.17 .17 0 0 1-.1 0 .17 .17 0 0 1-.1-.1z"/>
</g>
<g fill="none" stroke="#000" stroke-width=".33">
<circle cx="30.2" cy="7.4" r="6.6"/>
<circle cx="7.4" cy="24.9" r="6.6"/>
<circle cx="30.2" cy="42.5" r="6.6"/>
</g>
</svg>
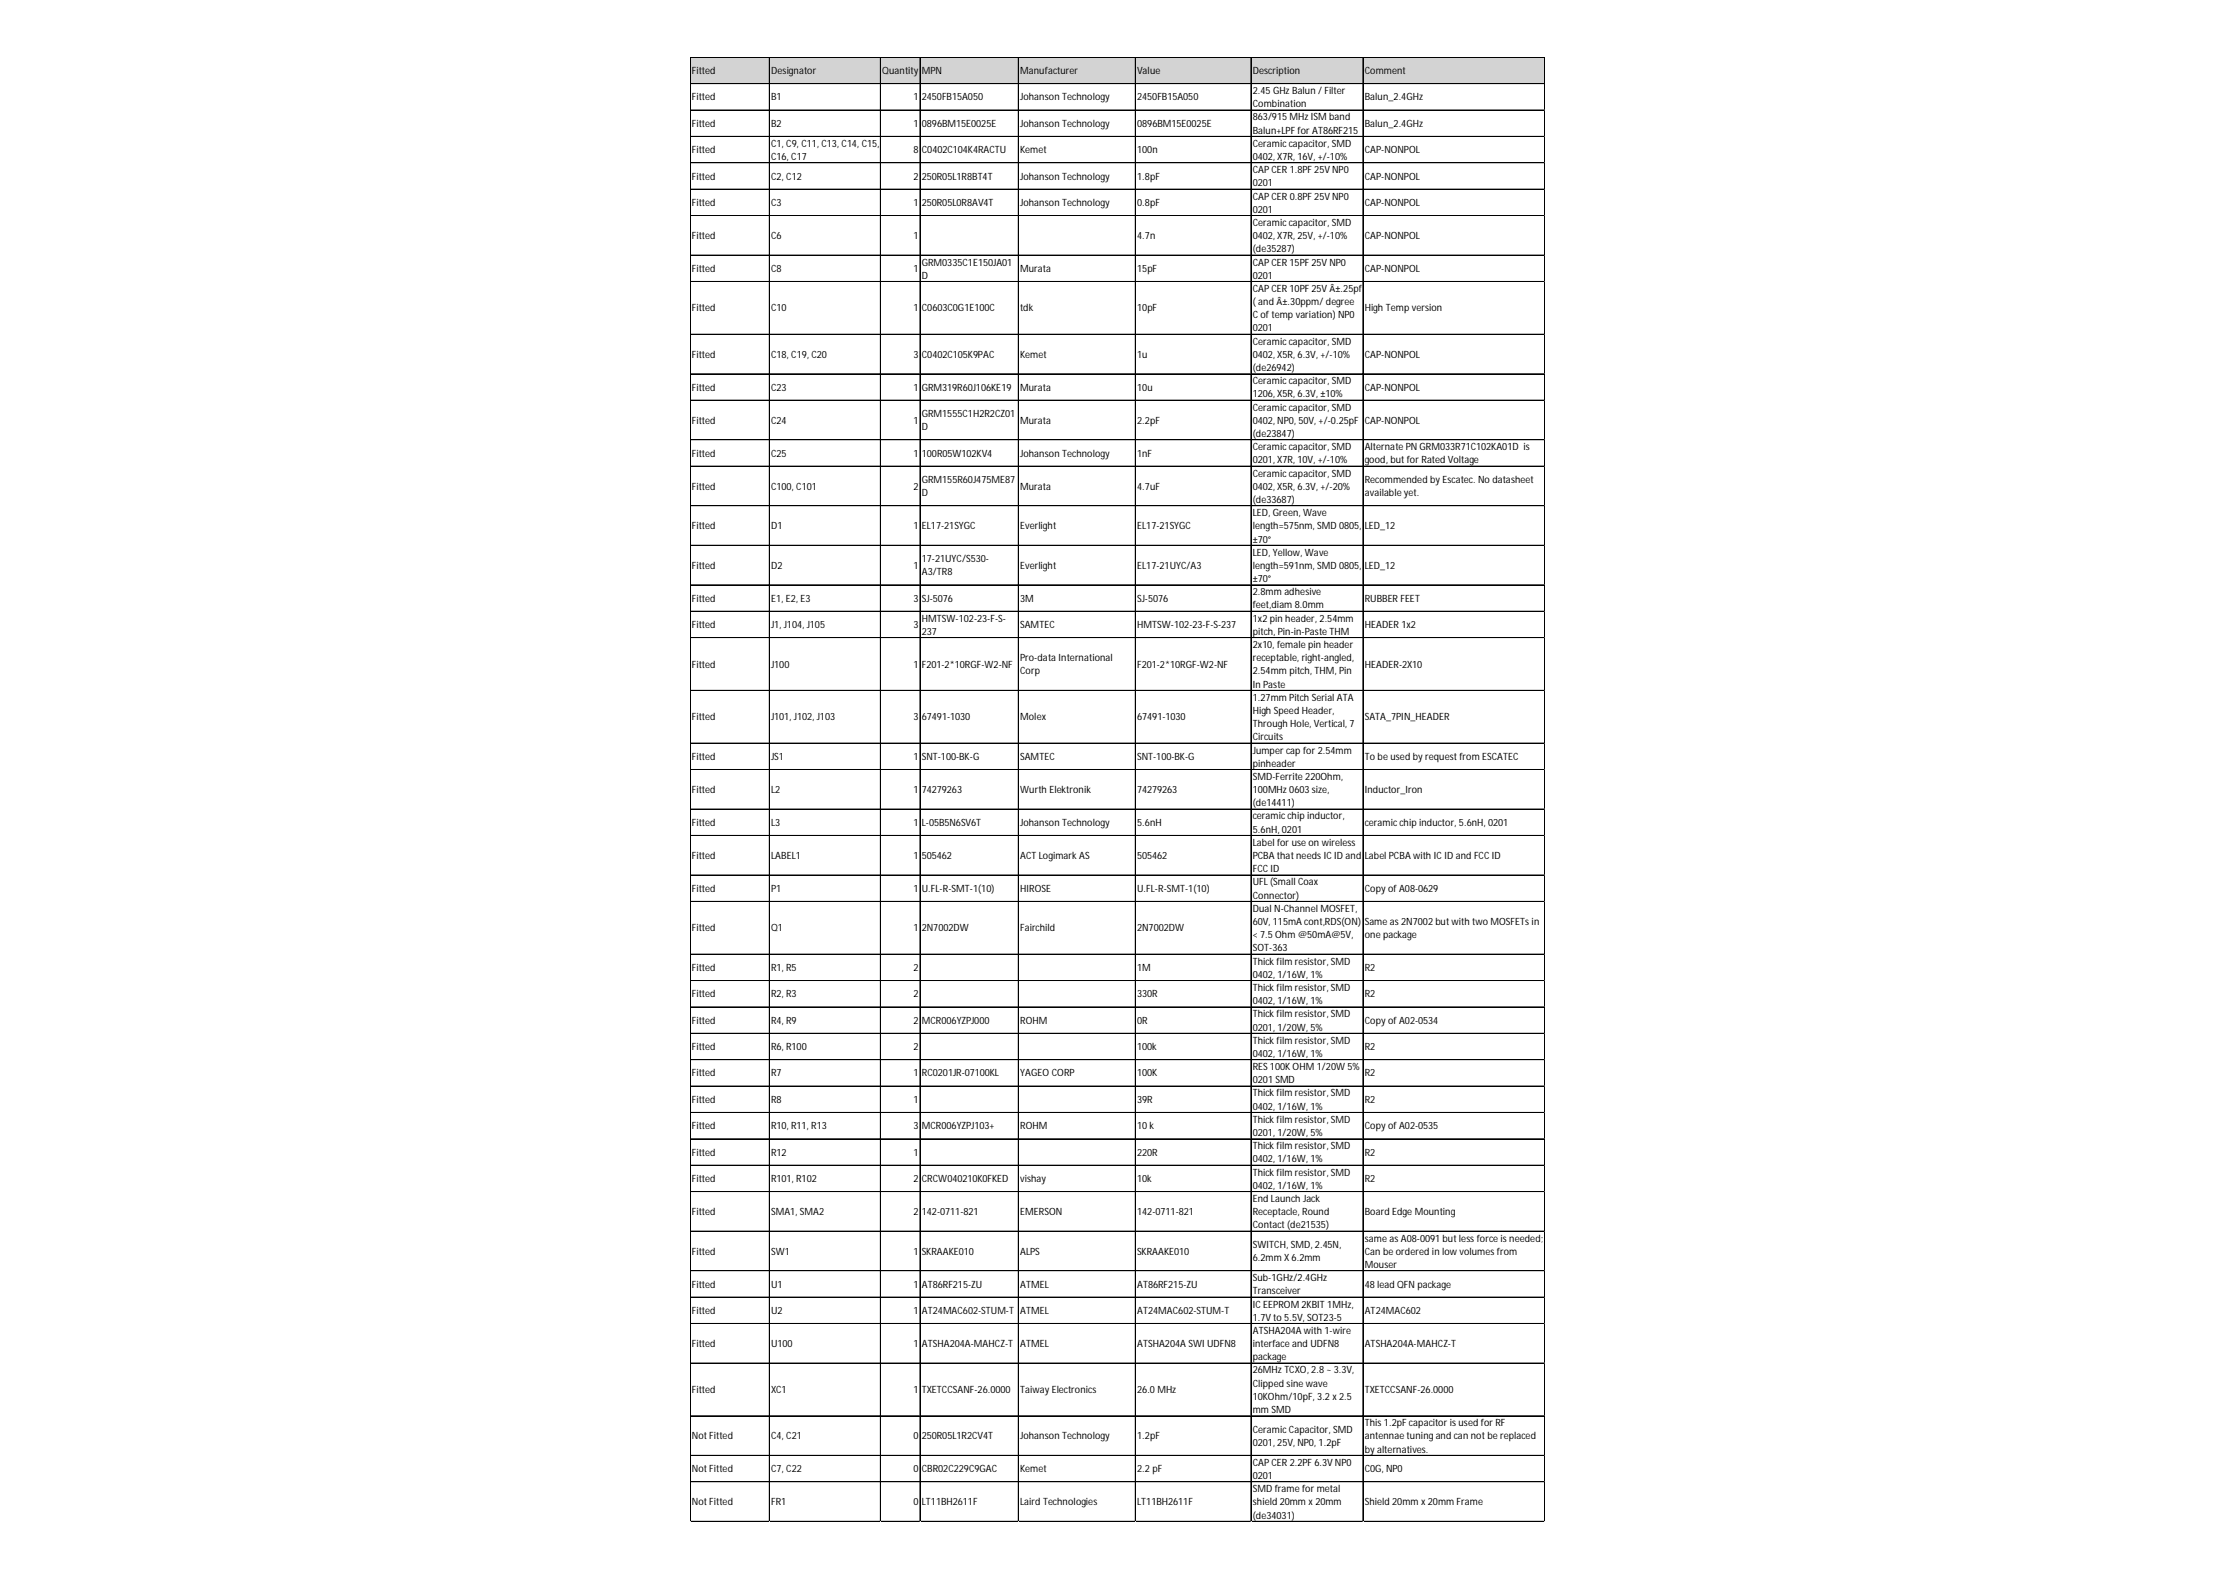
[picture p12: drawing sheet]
<svg xmlns="http://www.w3.org/2000/svg" width="297mm" height="210mm" viewBox="0 0 297 210" stroke-linecap="round" stroke-linejoin="round" font-family="sans-serif">
<defs><g id="words">
<g font-size="1.3">
<text x="91.8" y="9.8">Fitted</text>
<text x="102.3" y="9.8">Designator</text>
<text x="117.1" y="9.8">Quantity</text>
<text x="122.3" y="9.8">MPN</text>
<text x="135.4" y="9.8">Manufacturer</text>
<text x="150.9" y="9.8">Value</text>
<text x="166.3" y="9.8">Description</text>
<text x="181.1" y="9.8">Comment</text>
<text x="91.8" y="13.3">Fitted</text>
<text x="91.8" y="16.8">Fitted</text>
<text x="102.3" y="13.3">B1</text>
<text x="102.3" y="16.8">B2</text>
<text x="121.3" y="13.3">1</text>
<text x="121.3" y="16.8">1</text>
<text x="122.3" y="13.3">2450FB15A050</text>
<text x="122.3" y="16.8">0896BM15E0025E</text>
<text x="135.4" y="13.3">Johanson Technology</text>
<text x="135.4" y="16.8">Johanson Technology</text>
<text x="150.9" y="13.3">2450FB15A050</text>
<text x="150.9" y="16.8">0896BM15E0025E</text>
<text x="166.3" y="12.5">2.45 GHz Balun /Filter</text>
<text x="166.3" y="14.2">Combination</text>
<text x="166.3" y="16">863/915 MHz ISM band</text>
<text x="166.3" y="17.7">Balun+LPF for AT86RF215</text>
<text x="181.1" y="13.3">Balun_2.4GHz</text>
<text x="181.1" y="16.8">Balun_2.4GHz</text>
<text x="91.8" y="20.3">Fitted</text>
<text x="91.8" y="23.8">Fitted</text>
<text x="102.3" y="19.5">C1, C9, C11, C13, C14, C15,</text>
<text x="102.3" y="21.2">C16, C17</text>
<text x="102.3" y="23.8">C2, C12</text>
<text x="121.3" y="20.3">8</text>
<text x="121.3" y="23.8">2</text>
<text x="122.3" y="20.3">C0402C104K4RACTU</text>
<text x="122.3" y="23.8">250R05L1R8BT4T</text>
<text x="135.4" y="20.3">Kemet</text>
<text x="135.4" y="23.8">Johanson Technology</text>
<text x="150.9" y="20.3">100n</text>
<text x="150.9" y="23.8">1.8pF</text>
<text x="166.3" y="19.5">Ceramiccapacitor, SMD</text>
<text x="166.3" y="21.2">0402, X7R, 16V, +/-10%</text>
<text x="166.3" y="23">CAPCER 1.8PF 25V NP0</text>
<text x="181.1" y="20.3">CAP-NONPOL</text>
<text x="181.1" y="23.8">CAP-NONPOL</text>
<text x="91.8" y="27.3">Fitted</text>
<text x="102.3" y="27.3">C3</text>
<text x="121.3" y="27.3">1</text>
<text x="122.3" y="27.3">250R05L0R8AV4T</text>
<text x="135.4" y="27.3">Johanson Technology</text>
<text x="150.9" y="27.3">0.8pF</text>
<text x="166.3" y="24.7">0201</text>
<text x="166.3" y="26.5">CAPCER 0.8PF 25V NP0</text>
<text x="166.3" y="28.2">0201</text>
<text x="166.3" y="30">Ceramiccapacitor, SMD</text>
<text x="181.1" y="27.3">CAP-NONPOL</text>
<text x="91.8" y="31.7">Fitted</text>
<text x="102.3" y="31.7">C6</text>
<text x="121.3" y="31.7">1</text>
<text x="122.3" y="35.2">GRM0335C1E150JA01</text>
<text x="150.9" y="31.7">4.7n</text>
<text x="166.3" y="31.7">0402, X7R, 25V, +/-10%</text>
<text x="166.3" y="33.5">(de35287)</text>
<text x="166.3" y="35.2">CAPCER 15PF 25V NP0</text>
<text x="181.1" y="31.7">CAP-NONPOL</text>
<text x="91.8" y="36.1">Fitted</text>
<text x="91.8" y="41.3">Fitted</text>
<text x="102.3" y="36.1">C8</text>
<text x="102.3" y="41.3">C10</text>
<text x="121.3" y="36.1">1</text>
<text x="121.3" y="41.3">1</text>
<text x="122.3" y="37">D</text>
<text x="122.3" y="41.3">C0603C0G1E100C</text>
<text x="135.4" y="36.1">Murata</text>
<text x="135.4" y="41.3">tdk</text>
<text x="150.9" y="36.1">15pF</text>
<text x="150.9" y="41.3">10pF</text>
<text x="166.3" y="37">0201</text>
<text x="166.3" y="38.7">CAPCER 10PF 25V Â±.25pf</text>
<text x="166.3" y="40.5">( and Â±.30ppm/ degree</text>
<text x="181.1" y="36.1">CAP-NONPOL</text>
<text x="181.1" y="41.3">High Temp version</text>
<text x="91.8" y="47.5">Fitted</text>
<text x="102.3" y="47.5">C18, C19, C20</text>
<text x="121.3" y="47.5">3</text>
<text x="122.3" y="47.5">C0402C105K9PAC</text>
<text x="135.4" y="47.5">Kemet</text>
<text x="150.9" y="47.5">1u</text>
<text x="166.3" y="42.2">Coftemp variation) NP0</text>
<text x="166.3" y="44">0201</text>
<text x="166.3" y="45.7">Ceramiccapacitor, SMD</text>
<text x="166.3" y="47.5">0402, X5R, 6.3V, +/-10%</text>
<text x="181.1" y="47.5">CAP-NONPOL</text>
<text x="91.8" y="51.8">Fitted</text>
<text x="102.3" y="51.8">C23</text>
<text x="121.3" y="51.8">1</text>
<text x="122.3" y="51.8">GRM319R60J106KE19</text>
<text x="135.4" y="51.8">Murata</text>
<text x="150.9" y="51.8">10u</text>
<text x="166.3" y="49.2">(de26942)</text>
<text x="166.3" y="51">Ceramiccapacitor, SMD</text>
<text x="166.3" y="52.7">1206, X5R, 6.3V, ±10%</text>
<text x="181.1" y="51.8">CAP-NONPOL</text>
<text x="91.8" y="56.2">Fitted</text>
<text x="102.3" y="56.2">C24</text>
<text x="121.3" y="56.2">1</text>
<text x="122.3" y="55.3">GRM1555C1H2R2CZ01</text>
<text x="122.3" y="57.1">D</text>
<text x="135.4" y="56.2">Murata</text>
<text x="150.9" y="56.2">2.2pF</text>
<text x="166.3" y="54.5">Ceramiccapacitor, SMD</text>
<text x="166.3" y="56.2">0402, NP0, 50V, +/-0.25pF</text>
<text x="166.3" y="58">(de23847)</text>
<text x="166.3" y="59.7">Ceramiccapacitor, SMD</text>
<text x="181.1" y="56.2">CAP-NONPOL</text>
<text x="181.1" y="59.7">Alternate PN GRM033R71C102KA01D is</text>
<text x="91.8" y="60.6">Fitted</text>
<text x="91.8" y="65">Fitted</text>
<text x="102.3" y="60.6">C25</text>
<text x="102.3" y="65">C100, C101</text>
<text x="121.3" y="60.6">1</text>
<text x="121.3" y="65">2</text>
<text x="122.3" y="60.6">100R05W102KV4</text>
<text x="122.3" y="64.1">GRM155R60J475ME87</text>
<text x="122.3" y="65.8">D</text>
<text x="135.4" y="60.6">Johanson Technology</text>
<text x="135.4" y="65">Murata</text>
<text x="150.9" y="60.6">1nF</text>
<text x="150.9" y="65">4.7uF</text>
<text x="166.3" y="61.5">0201, X7R, 10V, +/-10%</text>
<text x="166.3" y="63.2">Ceramiccapacitor, SMD</text>
<text x="166.3" y="65">0402, X5R, 6.3V, +/-20%</text>
<text x="181.1" y="61.5">good, butfor Rated Voltage</text>
<text x="181.1" y="64.1">Recommended by Escatec. No datasheet</text>
<text x="181.1" y="65.8">available yet.</text>
<text x="91.8" y="70.2">Fitted</text>
<text x="102.3" y="70.2">D1</text>
<text x="121.3" y="70.2">1</text>
<text x="122.3" y="70.2">EL17-21SYGC</text>
<text x="135.4" y="70.2">Everlight</text>
<text x="150.9" y="70.2">EL17-21SYGC</text>
<text x="166.3" y="66.7">(de33687)</text>
<text x="166.3" y="68.5">LED, Green, Wave</text>
<text x="166.3" y="70.2">length=575nm, SMD 0805,</text>
<text x="166.3" y="72">±70°</text>
<text x="181.1" y="70.2">LED_12</text>
<text x="91.8" y="75.5">Fitted</text>
<text x="102.3" y="75.5">D2</text>
<text x="121.3" y="75.5">1</text>
<text x="122.3" y="74.6">17-21UYC/S530-</text>
<text x="122.3" y="76.3">A3/TR8</text>
<text x="135.4" y="75.5">Everlight</text>
<text x="150.9" y="75.5">EL17-21UYC/A3</text>
<text x="166.3" y="73.7">LED, Yellow, Wave</text>
<text x="166.3" y="75.5">length=591nm, SMD 0805,</text>
<text x="166.3" y="77.2">±70°</text>
<text x="181.1" y="75.5">LED_12</text>
<text x="91.8" y="79.8">Fitted</text>
<text x="91.8" y="83.3">Fitted</text>
<text x="102.3" y="79.8">E1, E2, E3</text>
<text x="102.3" y="83.3">J1, J104, J105</text>
<text x="121.3" y="79.8">3</text>
<text x="121.3" y="83.3">3</text>
<text x="122.3" y="79.8">SJ-5076</text>
<text x="122.3" y="82.5">HMTSW-102-23-F-S-</text>
<text x="135.4" y="79.8">3M</text>
<text x="135.4" y="83.3">SAMTEC</text>
<text x="150.9" y="79.8">SJ-5076</text>
<text x="150.9" y="83.3">HMTSW-102-23-F-S-237</text>
<text x="166.3" y="79">2.8mm adhesive</text>
<text x="166.3" y="80.7">feet,diam 8.0mm</text>
<text x="166.3" y="82.5">1x2 pin header, 2.54mm</text>
<text x="181.1" y="79.8">RUBBER FEET</text>
<text x="181.1" y="83.3">HEADER 1x2</text>
<text x="91.8" y="88.6">Fitted</text>
<text x="102.3" y="88.6">J100</text>
<text x="121.3" y="88.6">1</text>
<text x="122.3" y="84.2">237</text>
<text x="122.3" y="88.6">F201-2*10RGF-W2-NF</text>
<text x="135.4" y="87.7">Pro-data International</text>
<text x="135.4" y="89.5">Corp</text>
<text x="150.9" y="88.6">F201-2*10RGF-W2-NF</text>
<text x="166.3" y="84.2">pitch, Pin-in-Paste THM</text>
<text x="166.3" y="86">2x10, female pin header</text>
<text x="166.3" y="87.7">receptable, right-angled,</text>
<text x="166.3" y="89.5">2.54mm pitch, THM, Pin</text>
<text x="181.1" y="88.6">HEADER-2X10</text>
<text x="91.8" y="95.6">Fitted</text>
<text x="102.3" y="95.6">J101, J102, J103</text>
<text x="121.3" y="95.6">3</text>
<text x="122.3" y="95.6">67491-1030</text>
<text x="135.4" y="95.6">Molex</text>
<text x="150.9" y="95.6">67491-1030</text>
<text x="166.3" y="91.2">In Paste</text>
<text x="166.3" y="93">1.27mm Pitch Serial ATA</text>
<text x="166.3" y="94.7">High Speed Header,</text>
<text x="181.1" y="95.6">SATA_7PIN_HEADER</text>
<text x="91.8" y="100.8">Fitted</text>
<text x="102.3" y="100.8">JS1</text>
<text x="121.3" y="100.8">1</text>
<text x="122.3" y="100.8">SNT-100-BK-G</text>
<text x="135.4" y="100.8">SAMTEC</text>
<text x="150.9" y="100.8">SNT-100-BK-G</text>
<text x="166.3" y="96.5">Through Hole, Vertical, 7</text>
<text x="166.3" y="98.2">Circuits</text>
<text x="166.3" y="100">Jumper cap for 2.54mm</text>
<text x="166.3" y="101.7">pinheader</text>
<text x="181.1" y="100.8">To be used by requestfrom ESCATEC</text>
<text x="91.8" y="105.2">Fitted</text>
<text x="102.3" y="105.2">L2</text>
<text x="121.3" y="105.2">1</text>
<text x="122.3" y="105.2">74279263</text>
<text x="135.4" y="105.2">Wurth Elektronik</text>
<text x="150.9" y="105.2">74279263</text>
<text x="166.3" y="103.5">SMD-Ferrite 220Ohm,</text>
<text x="166.3" y="105.2">100MHz 0603 size,</text>
<text x="166.3" y="107">(de14411)</text>
<text x="181.1" y="105.2">Inductor_Iron</text>
<text x="91.8" y="109.6">Fitted</text>
<text x="91.8" y="114">Fitted</text>
<text x="102.3" y="109.6">L3</text>
<text x="102.3" y="114">LABEL1</text>
<text x="121.3" y="109.6">1</text>
<text x="121.3" y="114">1</text>
<text x="122.3" y="109.6">L-05B5N6SV6T</text>
<text x="122.3" y="114">505462</text>
<text x="135.4" y="109.6">Johanson Technology</text>
<text x="135.4" y="114">ACT Logimark AS</text>
<text x="150.9" y="109.6">5.6nH</text>
<text x="150.9" y="114">505462</text>
<text x="166.3" y="108.7">ceramicchip inductor,</text>
<text x="166.3" y="110.5">5.6nH, 0201</text>
<text x="166.3" y="112.2">Label for use on wireless</text>
<text x="166.3" y="114">PCBA that needsICID and</text>
<text x="181.1" y="109.6">ceramicchip inductor, 5.6nH, 0201</text>
<text x="181.1" y="114">Label PCBA with ICID and FCCID</text>
<text x="91.8" y="118.3">Fitted</text>
<text x="102.3" y="118.3">P1</text>
<text x="121.3" y="118.3">1</text>
<text x="122.3" y="118.3">U.FL-R-SMT-1(10)</text>
<text x="135.4" y="118.3">HIROSE</text>
<text x="150.9" y="118.3">U.FL-R-SMT-1(10)</text>
<text x="166.3" y="115.7">FCCID</text>
<text x="166.3" y="117.5">UFL(Small Coax</text>
<text x="166.3" y="119.2">Connector)</text>
<text x="181.1" y="118.3">Copy ofA08-0629</text>
<text x="91.8" y="123.6">Fitted</text>
<text x="102.3" y="123.6">Q1</text>
<text x="121.3" y="123.6">1</text>
<text x="122.3" y="123.6">2N7002DW</text>
<text x="135.4" y="123.6">Fairchild</text>
<text x="150.9" y="123.6">2N7002DW</text>
<text x="166.3" y="121">Dual N-Channel MOSFET,</text>
<text x="166.3" y="122.7">60V, 115mA cont,RDS(ON)</text>
<text x="166.3" y="124.5">&lt; 7.5 Ohm @50mA@5V,</text>
<text x="181.1" y="122.7">Same as2N7002 butwith two MOSFETsin</text>
<text x="181.1" y="124.5">one package</text>
<text x="91.8" y="128.8">Fitted</text>
<text x="102.3" y="128.8">R1, R5</text>
<text x="121.3" y="128.8">2</text>
<text x="150.9" y="128.8">1M</text>
<text x="166.3" y="126.2">SOT-363</text>
<text x="166.3" y="128">Thick film resistor, SMD</text>
<text x="166.3" y="129.7">0402, 1/16W, 1%</text>
<text x="166.3" y="131.5">Thick film resistor, SMD</text>
<text x="181.1" y="128.8">R2</text>
<text x="91.8" y="132.3">Fitted</text>
<text x="91.8" y="135.8">Fitted</text>
<text x="102.3" y="132.3">R2, R3</text>
<text x="102.3" y="135.8">R4, R9</text>
<text x="121.3" y="132.3">2</text>
<text x="121.3" y="135.8">2</text>
<text x="122.3" y="135.8">MCR006YZPJ000</text>
<text x="135.4" y="135.8">ROHM</text>
<text x="150.9" y="132.3">330R</text>
<text x="150.9" y="135.8">0R</text>
<text x="166.3" y="133.2">0402, 1/16W, 1%</text>
<text x="166.3" y="135">Thick film resistor, SMD</text>
<text x="166.3" y="136.7">0201, 1/20W, 5%</text>
<text x="181.1" y="132.3">R2</text>
<text x="181.1" y="135.8">Copy ofA02-0534</text>
<text x="91.8" y="139.3">Fitted</text>
<text x="91.8" y="142.8">Fitted</text>
<text x="102.3" y="139.3">R6, R100</text>
<text x="102.3" y="142.8">R7</text>
<text x="121.3" y="139.3">2</text>
<text x="121.3" y="142.8">1</text>
<text x="122.3" y="142.8">RC0201JR-07100KL</text>
<text x="135.4" y="142.8">YAGEO CORP</text>
<text x="150.9" y="139.3">100k</text>
<text x="150.9" y="142.8">100K</text>
<text x="166.3" y="138.5">Thick film resistor, SMD</text>
<text x="166.3" y="140.2">0402, 1/16W, 1%</text>
<text x="166.3" y="142">RES 100K OHM 1/20W5%</text>
<text x="166.3" y="143.7">0201 SMD</text>
<text x="181.1" y="139.3">R2</text>
<text x="181.1" y="142.8">R2</text>
<text x="91.8" y="146.3">Fitted</text>
<text x="91.8" y="149.8">Fitted</text>
<text x="102.3" y="146.3">R8</text>
<text x="102.3" y="149.8">R10, R11, R13</text>
<text x="121.3" y="146.3">1</text>
<text x="121.3" y="149.8">3</text>
<text x="122.3" y="149.8">MCR006YZPJ103+</text>
<text x="135.4" y="149.8">ROHM</text>
<text x="150.9" y="146.3">39R</text>
<text x="150.9" y="149.8">10 k</text>
<text x="166.3" y="145.5">Thick film resistor, SMD</text>
<text x="166.3" y="147.2">0402, 1/16W, 1%</text>
<text x="166.3" y="149">Thick film resistor, SMD</text>
<text x="181.1" y="146.3">R2</text>
<text x="181.1" y="149.8">Copy ofA02-0535</text>
<text x="91.8" y="153.3">Fitted</text>
<text x="102.3" y="153.3">R12</text>
<text x="121.3" y="153.3">1</text>
<text x="150.9" y="153.3">220R</text>
<text x="166.3" y="150.7">0201, 1/20W, 5%</text>
<text x="166.3" y="152.5">Thick film resistor, SMD</text>
<text x="166.3" y="154.2">0402, 1/16W, 1%</text>
<text x="166.3" y="156">Thick film resistor, SMD</text>
<text x="181.1" y="153.3">R2</text>
<text x="91.8" y="156.8">Fitted</text>
<text x="91.8" y="161.2">Fitted</text>
<text x="102.3" y="156.8">R101, R102</text>
<text x="102.3" y="161.2">SMA1, SMA2</text>
<text x="121.3" y="156.8">2</text>
<text x="121.3" y="161.2">2</text>
<text x="122.3" y="156.8">CRCW040210K0FKED</text>
<text x="122.3" y="161.2">142-0711-821</text>
<text x="135.4" y="156.8">vishay</text>
<text x="135.4" y="161.2">EMERSON</text>
<text x="150.9" y="156.8">10k</text>
<text x="150.9" y="161.2">142-0711-821</text>
<text x="166.3" y="157.7">0402, 1/16W, 1%</text>
<text x="166.3" y="159.5">End Launch Jack</text>
<text x="166.3" y="161.2">Receptacle, Round</text>
<text x="181.1" y="156.8">R2</text>
<text x="181.1" y="161.2">Board Edge Mounting</text>
<text x="91.8" y="166.5">Fitted</text>
<text x="102.3" y="166.5">SW1</text>
<text x="121.3" y="166.5">1</text>
<text x="122.3" y="166.5">SKRAAKE010</text>
<text x="135.4" y="166.5">ALPS</text>
<text x="150.9" y="166.5">SKRAAKE010</text>
<text x="166.3" y="163">Contact(de21535)</text>
<text x="166.3" y="165.6">SWITCH, SMD, 2.45N,</text>
<text x="166.3" y="167.3">6.2mm X6.2mm</text>
<text x="181.1" y="164.7">same asA08-0091 butlessforce isneeded;</text>
<text x="181.1" y="166.5">Can be ordered in lowvolumesfrom</text>
<text x="91.8" y="170.8">Fitted</text>
<text x="102.3" y="170.8">U1</text>
<text x="121.3" y="170.8">1</text>
<text x="122.3" y="170.8">AT86RF215-ZU</text>
<text x="135.4" y="170.8">ATMEL</text>
<text x="150.9" y="170.8">AT86RF215-ZU</text>
<text x="166.3" y="170">Sub-1GHz/2.4GHz</text>
<text x="166.3" y="171.7">Transceiver</text>
<text x="166.3" y="173.5">ICEEPROM 2KBIT 1MHz,</text>
<text x="181.1" y="168.2">Mouser</text>
<text x="181.1" y="170.8">48 lead QFN package</text>
<text x="91.8" y="174.3">Fitted</text>
<text x="91.8" y="178.7">Fitted</text>
<text x="102.3" y="174.3">U2</text>
<text x="102.3" y="178.7">U100</text>
<text x="121.3" y="174.3">1</text>
<text x="121.3" y="178.7">1</text>
<text x="122.3" y="174.3">AT24MAC602-STUM-T</text>
<text x="122.3" y="178.7">ATSHA204A-MAHCZ-T</text>
<text x="135.4" y="174.3">ATMEL</text>
<text x="135.4" y="178.7">ATMEL</text>
<text x="150.9" y="174.3">AT24MAC602-STUM-T</text>
<text x="150.9" y="178.7">ATSHA204A SWI UDFN8</text>
<text x="166.3" y="175.2">1.7V to 5.5V, SOT23-5</text>
<text x="166.3" y="177">ATSHA204A with 1-wire</text>
<text x="166.3" y="178.7">interface and UDFN8</text>
<text x="181.1" y="174.3">AT24MAC602</text>
<text x="181.1" y="178.7">ATSHA204A-MAHCZ-T</text>
<text x="91.8" y="184.8">Fitted</text>
<text x="102.3" y="184.8">XC1</text>
<text x="121.3" y="184.8">1</text>
<text x="122.3" y="184.8">TXETCCSANF-26.0000</text>
<text x="135.4" y="184.8">Taiway Electronics</text>
<text x="150.9" y="184.8">26.0 MHz</text>
<text x="166.3" y="180.5">package</text>
<text x="166.3" y="182.2">26MHz TCXO, 2.8 ~ 3.3V,</text>
<text x="166.3" y="184">Clipped sine wave</text>
<text x="166.3" y="185.7">10KOhm/10pF, 3.2 x 2.5</text>
<text x="181.1" y="184.8">TXETCCSANF-26.0000</text>
<text x="91.8" y="191">NotFitted</text>
<text x="102.3" y="191">C4, C21</text>
<text x="121.3" y="191">0</text>
<text x="122.3" y="191">250R05L1R2CV4T</text>
<text x="135.4" y="191">Johanson Technology</text>
<text x="150.9" y="191">1.2pF</text>
<text x="166.3" y="187.5">mm SMD</text>
<text x="166.3" y="190.1">CeramicCapacitor, SMD</text>
<text x="166.3" y="191.8">0201, 25V, NP0, 1.2pF</text>
<text x="181.1" y="189.2">This1.2pF capacitor isused for RF</text>
<text x="181.1" y="191">antennae tuningand can not be replaced</text>
<text x="91.8" y="195.3">NotFitted</text>
<text x="102.3" y="195.3">C7, C22</text>
<text x="121.3" y="195.3">0</text>
<text x="122.3" y="195.3">CBR02C229C9GAC</text>
<text x="135.4" y="195.3">Kemet</text>
<text x="150.9" y="195.3">2.2 pF</text>
<text x="166.3" y="194.5">CAPCER 2.2PF 6.3V NP0</text>
<text x="166.3" y="196.2">0201</text>
<text x="166.3" y="198">SMD frame for metal</text>
<text x="181.1" y="192.7">by alternatives.</text>
<text x="181.1" y="195.3">C0G, NP0</text>
<text x="91.8" y="199.7">NotFitted</text>
<text x="102.3" y="199.7">FR1</text>
<text x="121.3" y="199.7">0</text>
<text x="122.3" y="199.7">LT11BH2611F</text>
<text x="135.4" y="199.7">Laird Technologies</text>
<text x="150.9" y="199.7">LT11BH2611F</text>
<text x="166.3" y="199.7">shield 20mm x 20mm</text>
<text x="166.3" y="201.5">(de34031)</text>
<text x="181.1" y="199.7">Shield 20mm x 20mm Frame</text>
</g>
</g></defs>
<path d="M91.6 7.6h113.5v3.6h-113.5z" fill="#d3d3d3"/>
<g fill="none" stroke="#000" stroke-width=".13">
<path d="M91.6 7.6v194.3M91.7 7.6h113.4M91.7 11.1h113.4M91.7 14.6h113.4M91.7 18.1h113.4M102.1 7.7v194.2M116.8 7.7v194.2M116.9 7.7v194.2M122.1 7.7v194.2M135.2 7.7v194.2M150.7 7.7v194.2M166 7.7v194.2"/>
<path d="M166.1 7.7v194.2M180.9 7.7v194.2M205 7.7v194.2M91.7 21.6h113.4M91.7 25.1h113.4M91.7 28.6h113.4M91.7 33.8h113.4M91.7 33.9h113.4M91.7 37.3h113.4M91.7 37.4h113.4M91.7 44.3h113.4M91.7 44.4h113.4"/>
<path d="M91.7 49.6h113.4M91.7 53.1h113.4M91.7 58.3h113.4M91.7 58.4h113.4M91.7 61.8h113.4M91.7 61.9h113.4M91.7 67.1h113.4M91.7 72.3h113.4M91.7 72.4h113.4M205.1 77.6h-113.4M91.7 81.1h113.4M91.7 91.6h113.4"/>
<path d="M91.7 98.6h113.4M205.1 84.6h-113.4M91.7 102.1h113.4M91.7 107.3h113.4M91.7 107.4h113.4M91.7 110.8h113.4M91.7 110.9h113.4M91.7 116.1h113.4M91.7 119.6h113.4M91.7 126.6h113.4M91.7 130.1h113.4M91.7 133.6h113.4"/>
<path d="M91.7 137.1h113.4M91.7 140.6h113.4M91.7 144.1h113.4M91.7 147.6h113.4M91.7 151.1h113.4M91.7 154.6h113.4M91.7 158.1h113.4M91.7 163.3h113.4M91.7 163.4h113.4M91.7 168.6h113.4M91.7 172.1h113.4M91.7 175.6h113.4"/>
<path d="M91.7 180.8h113.4M91.7 180.9h113.4M91.7 187.8h113.4M91.7 187.9h113.4M91.7 196.6h113.4M205.1 193.1h-113.4M91.7 201.8h113.4M91.7 201.9h113.4"/>
</g>
<path d="M91.6 201.9v.1" fill="none" stroke="#d4d4d4" stroke-width=".13"/>
<path d="M91.6 201.9l.1 .1z" fill="#d4d4d4"/>
<path d="M102.1 201.9v.1" fill="none" stroke="#d4d4d4" stroke-width=".13"/>
<path d="M102.1 201.9l.1 .1z" fill="#d4d4d4"/>
<path d="M116.8 201.9v.1" fill="none" stroke="#d4d4d4" stroke-width=".13"/>
<path d="M116.8 201.9l.1 .1z" fill="#d4d4d4"/>
<path d="M122.1 201.9v.1" fill="none" stroke="#d4d4d4" stroke-width=".13"/>
<path d="M122.1 201.9l.1 .1z" fill="#d4d4d4"/>
<path d="M135.2 201.9v.1" fill="none" stroke="#d4d4d4" stroke-width=".13"/>
<path d="M135.2 201.9v.1z" fill="#d4d4d4"/>
<path d="M150.7 201.9v.1" fill="none" stroke="#d4d4d4" stroke-width=".13"/>
<path d="M150.7 201.9v.1z" fill="#d4d4d4"/>
<path d="M166 201.9v.1" fill="none" stroke="#d4d4d4" stroke-width=".13"/>
<path d="M166 201.9l.1 .1z" fill="#d4d4d4"/>
<path d="M180.9 201.9v.1" fill="none" stroke="#d4d4d4" stroke-width=".13"/>
<path d="M180.9 201.9l.1 .1z" fill="#d4d4d4"/>
<path d="M205 201.9v.1" fill="none" stroke="#d4d4d4" stroke-width=".13"/>
<path d="M205 201.9l.1 .1z" fill="#d4d4d4"/>
<path d="M205.1 14.6h.1" fill="none" stroke="#d4d4d4" stroke-width=".13"/>
<path d="M205.1 14.6v.1z" fill="#d4d4d4"/>
<path d="M205.1 18.1h.1" fill="none" stroke="#d4d4d4" stroke-width=".13"/>
<path d="M205.1 18.1v.1z" fill="#d4d4d4"/>
<path d="M205.1 21.6h.1" fill="none" stroke="#d4d4d4" stroke-width=".13"/>
<path d="M205.1 21.6v.1z" fill="#d4d4d4"/>
<path d="M205.1 25.1h.1" fill="none" stroke="#d4d4d4" stroke-width=".13"/>
<path d="M205.1 25.1v.1z" fill="#d4d4d4"/>
<path d="M205.1 28.6h.1" fill="none" stroke="#d4d4d4" stroke-width=".13"/>
<path d="M205.1 28.6v.1z" fill="#d4d4d4"/>
<path d="M205.1 33.8h.1" fill="none" stroke="#d4d4d4" stroke-width=".13"/>
<path d="M205.1 33.8v.1z" fill="#d4d4d4"/>
<path d="M205.1 37.3h.1" fill="none" stroke="#d4d4d4" stroke-width=".13"/>
<path d="M205.1 37.3v.1z" fill="#d4d4d4"/>
<path d="M205.1 44.3h.1" fill="none" stroke="#d4d4d4" stroke-width=".13"/>
<path d="M205.1 44.3v.1z" fill="#d4d4d4"/>
<path d="M205.1 49.6h.1" fill="none" stroke="#d4d4d4" stroke-width=".13"/>
<path d="M205.1 49.6v.1z" fill="#d4d4d4"/>
<path d="M205.1 53.1h.1" fill="none" stroke="#d4d4d4" stroke-width=".13"/>
<path d="M205.1 53.1v.1z" fill="#d4d4d4"/>
<path d="M205.1 58.3h.1" fill="none" stroke="#d4d4d4" stroke-width=".13"/>
<path d="M205.1 58.3v.1z" fill="#d4d4d4"/>
<path d="M205.1 61.8h.1" fill="none" stroke="#d4d4d4" stroke-width=".13"/>
<path d="M205.1 61.8v.1z" fill="#d4d4d4"/>
<path d="M205.1 67.1h.1" fill="none" stroke="#d4d4d4" stroke-width=".13"/>
<path d="M205.1 67.1v.1z" fill="#d4d4d4"/>
<path d="M205.1 72.3h.1" fill="none" stroke="#d4d4d4" stroke-width=".13"/>
<path d="M205.1 72.3v.1z" fill="#d4d4d4"/>
<path d="M205.1 77.6h.1" fill="none" stroke="#d4d4d4" stroke-width=".13"/>
<path d="M205.1 77.6v.1z" fill="#d4d4d4"/>
<path d="M205.1 81.1h.1" fill="none" stroke="#d4d4d4" stroke-width=".13"/>
<path d="M205.1 81.1v.1z" fill="#d4d4d4"/>
<path d="M205.1 84.6h.1" fill="none" stroke="#d4d4d4" stroke-width=".13"/>
<path d="M205.1 84.6v.1z" fill="#d4d4d4"/>
<path d="M205.1 91.6h.1" fill="none" stroke="#d4d4d4" stroke-width=".13"/>
<path d="M205.1 91.6v.1z" fill="#d4d4d4"/>
<path d="M205.1 98.6h.1" fill="none" stroke="#d4d4d4" stroke-width=".13"/>
<path d="M205.1 98.6v.1z" fill="#d4d4d4"/>
<path d="M205.1 102.1h.1" fill="none" stroke="#d4d4d4" stroke-width=".13"/>
<path d="M205.1 102.1v.1z" fill="#d4d4d4"/>
<path d="M205.1 107.3h.1" fill="none" stroke="#d4d4d4" stroke-width=".13"/>
<path d="M205.1 107.3v.1z" fill="#d4d4d4"/>
<path d="M205.1 110.8h.1" fill="none" stroke="#d4d4d4" stroke-width=".13"/>
<path d="M205.1 110.8v.1z" fill="#d4d4d4"/>
<path d="M205.1 116.1h.1" fill="none" stroke="#d4d4d4" stroke-width=".13"/>
<path d="M205.1 116.1v.1z" fill="#d4d4d4"/>
<path d="M205.1 119.6h.1" fill="none" stroke="#d4d4d4" stroke-width=".13"/>
<path d="M205.1 119.6v.1z" fill="#d4d4d4"/>
<path d="M205.1 126.6h.1" fill="none" stroke="#d4d4d4" stroke-width=".13"/>
<path d="M205.1 126.6v.1z" fill="#d4d4d4"/>
<path d="M205.1 130.1h.1" fill="none" stroke="#d4d4d4" stroke-width=".13"/>
<path d="M205.1 130.1v.1z" fill="#d4d4d4"/>
<path d="M205.1 133.6h.1" fill="none" stroke="#d4d4d4" stroke-width=".13"/>
<path d="M205.1 133.6v.1z" fill="#d4d4d4"/>
<path d="M205.1 137.1h.1" fill="none" stroke="#d4d4d4" stroke-width=".13"/>
<path d="M205.1 137.1v.1z" fill="#d4d4d4"/>
<path d="M205.1 140.6h.1" fill="none" stroke="#d4d4d4" stroke-width=".13"/>
<path d="M205.1 140.6v.1z" fill="#d4d4d4"/>
<path d="M205.1 144.1h.1" fill="none" stroke="#d4d4d4" stroke-width=".13"/>
<path d="M205.1 144.1v.1z" fill="#d4d4d4"/>
<path d="M205.1 147.6h.1" fill="none" stroke="#d4d4d4" stroke-width=".13"/>
<path d="M205.1 147.6v.1z" fill="#d4d4d4"/>
<path d="M205.1 151.1h.1" fill="none" stroke="#d4d4d4" stroke-width=".13"/>
<path d="M205.1 151.1v.1z" fill="#d4d4d4"/>
<path d="M205.1 154.6h.1" fill="none" stroke="#d4d4d4" stroke-width=".13"/>
<path d="M205.1 154.6v.1z" fill="#d4d4d4"/>
<path d="M205.1 158.1h.1" fill="none" stroke="#d4d4d4" stroke-width=".13"/>
<path d="M205.1 158.1v.1z" fill="#d4d4d4"/>
<path d="M205.1 163.3h.1" fill="none" stroke="#d4d4d4" stroke-width=".13"/>
<path d="M205.1 163.3v.1z" fill="#d4d4d4"/>
<path d="M205.1 168.6h.1" fill="none" stroke="#d4d4d4" stroke-width=".13"/>
<path d="M205.1 168.6v.1z" fill="#d4d4d4"/>
<path d="M205.1 172.1h.1" fill="none" stroke="#d4d4d4" stroke-width=".13"/>
<path d="M205.1 172.1v.1z" fill="#d4d4d4"/>
<path d="M205.1 175.6h.1" fill="none" stroke="#d4d4d4" stroke-width=".13"/>
<path d="M205.1 175.6v.1z" fill="#d4d4d4"/>
<path d="M205.1 180.8h.1" fill="none" stroke="#d4d4d4" stroke-width=".13"/>
<path d="M205.1 180.8v.1z" fill="#d4d4d4"/>
<path d="M205.1 187.8h.1" fill="none" stroke="#d4d4d4" stroke-width=".13"/>
<path d="M205.1 187.8v.1z" fill="#d4d4d4"/>
<path d="M205.1 193.1h.1" fill="none" stroke="#d4d4d4" stroke-width=".13"/>
<path d="M205.1 193.1v.1z" fill="#d4d4d4"/>
<path d="M205.1 196.6h.1" fill="none" stroke="#d4d4d4" stroke-width=".13"/>
<path d="M205.1 196.6v.1z" fill="#d4d4d4"/>
<path d="M205.1 201.8h.1" fill="none" stroke="#d4d4d4" stroke-width=".13"/>
<path d="M205.1 201.8v.1z" fill="#d4d4d4"/>
<use href="#words"/>
</svg>
